VERSION 5.7 ;
BUSBITCHARS "[]" ;
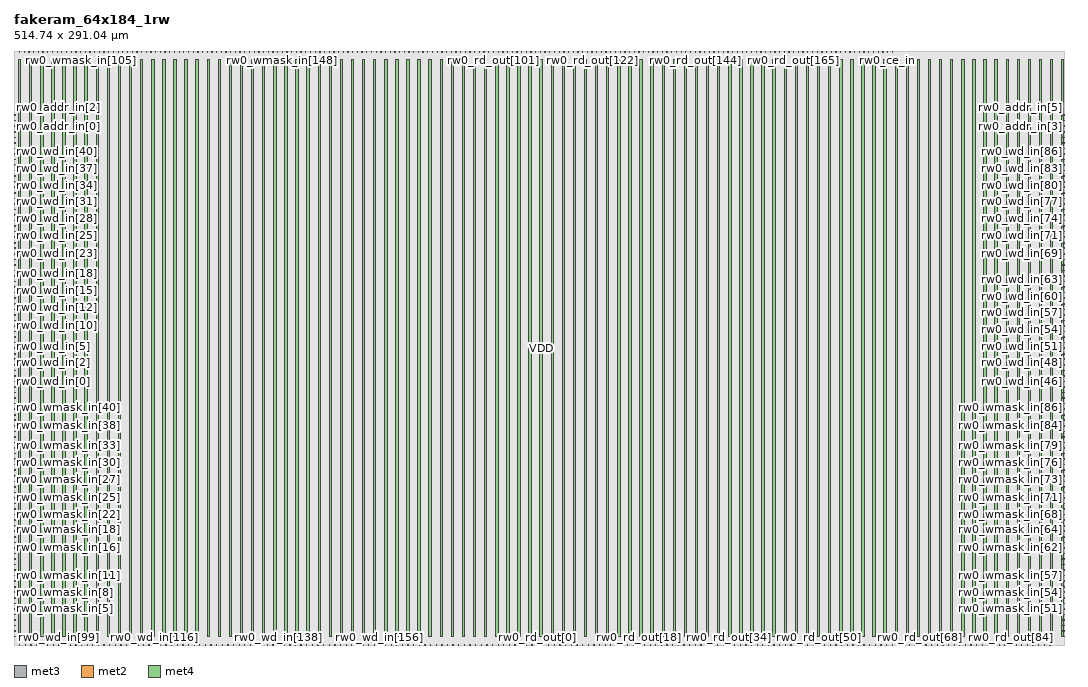
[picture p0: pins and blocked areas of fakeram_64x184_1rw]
MACRO fakeram_64x184_1rw
  FOREIGN fakeram_64x184_1rw 0 0 ;
  SYMMETRY X Y R90 ;
  SIZE 514.740 BY 291.040 ;
  CLASS BLOCK ;
  PIN rw0_wmask_in[0]
    DIRECTION INPUT ;
    USE SIGNAL ;
    SHAPE ABUTMENT ;
    PORT
      LAYER met3 ;
      RECT 0.000 3.930 0.900 4.230 ;
    END
  END rw0_wmask_in[0]
  PIN rw0_wmask_in[1]
    DIRECTION INPUT ;
    USE SIGNAL ;
    SHAPE ABUTMENT ;
    PORT
      LAYER met3 ;
      RECT 0.000 6.650 0.900 6.950 ;
    END
  END rw0_wmask_in[1]
  PIN rw0_wmask_in[2]
    DIRECTION INPUT ;
    USE SIGNAL ;
    SHAPE ABUTMENT ;
    PORT
      LAYER met3 ;
      RECT 0.000 9.370 0.900 9.670 ;
    END
  END rw0_wmask_in[2]
  PIN rw0_wmask_in[3]
    DIRECTION INPUT ;
    USE SIGNAL ;
    SHAPE ABUTMENT ;
    PORT
      LAYER met3 ;
      RECT 0.000 12.090 0.900 12.390 ;
    END
  END rw0_wmask_in[3]
  PIN rw0_wmask_in[4]
    DIRECTION INPUT ;
    USE SIGNAL ;
    SHAPE ABUTMENT ;
    PORT
      LAYER met3 ;
      RECT 0.000 14.810 0.900 15.110 ;
    END
  END rw0_wmask_in[4]
  PIN rw0_wmask_in[5]
    DIRECTION INPUT ;
    USE SIGNAL ;
    SHAPE ABUTMENT ;
    PORT
      LAYER met3 ;
      RECT 0.000 17.530 0.900 17.830 ;
    END
  END rw0_wmask_in[5]
  PIN rw0_wmask_in[6]
    DIRECTION INPUT ;
    USE SIGNAL ;
    SHAPE ABUTMENT ;
    PORT
      LAYER met3 ;
      RECT 0.000 20.250 0.900 20.550 ;
    END
  END rw0_wmask_in[6]
  PIN rw0_wmask_in[7]
    DIRECTION INPUT ;
    USE SIGNAL ;
    SHAPE ABUTMENT ;
    PORT
      LAYER met3 ;
      RECT 0.000 22.970 0.900 23.270 ;
    END
  END rw0_wmask_in[7]
  PIN rw0_wmask_in[8]
    DIRECTION INPUT ;
    USE SIGNAL ;
    SHAPE ABUTMENT ;
    PORT
      LAYER met3 ;
      RECT 0.000 25.690 0.900 25.990 ;
    END
  END rw0_wmask_in[8]
  PIN rw0_wmask_in[9]
    DIRECTION INPUT ;
    USE SIGNAL ;
    SHAPE ABUTMENT ;
    PORT
      LAYER met3 ;
      RECT 0.000 28.410 0.900 28.710 ;
    END
  END rw0_wmask_in[9]
  PIN rw0_wmask_in[10]
    DIRECTION INPUT ;
    USE SIGNAL ;
    SHAPE ABUTMENT ;
    PORT
      LAYER met3 ;
      RECT 0.000 31.130 0.900 31.430 ;
    END
  END rw0_wmask_in[10]
  PIN rw0_wmask_in[11]
    DIRECTION INPUT ;
    USE SIGNAL ;
    SHAPE ABUTMENT ;
    PORT
      LAYER met3 ;
      RECT 0.000 33.850 0.900 34.150 ;
    END
  END rw0_wmask_in[11]
  PIN rw0_wmask_in[12]
    DIRECTION INPUT ;
    USE SIGNAL ;
    SHAPE ABUTMENT ;
    PORT
      LAYER met3 ;
      RECT 0.000 36.570 0.900 36.870 ;
    END
  END rw0_wmask_in[12]
  PIN rw0_wmask_in[13]
    DIRECTION INPUT ;
    USE SIGNAL ;
    SHAPE ABUTMENT ;
    PORT
      LAYER met3 ;
      RECT 0.000 39.290 0.900 39.590 ;
    END
  END rw0_wmask_in[13]
  PIN rw0_wmask_in[14]
    DIRECTION INPUT ;
    USE SIGNAL ;
    SHAPE ABUTMENT ;
    PORT
      LAYER met3 ;
      RECT 0.000 42.010 0.900 42.310 ;
    END
  END rw0_wmask_in[14]
  PIN rw0_wmask_in[15]
    DIRECTION INPUT ;
    USE SIGNAL ;
    SHAPE ABUTMENT ;
    PORT
      LAYER met3 ;
      RECT 0.000 44.730 0.900 45.030 ;
    END
  END rw0_wmask_in[15]
  PIN rw0_wmask_in[16]
    DIRECTION INPUT ;
    USE SIGNAL ;
    SHAPE ABUTMENT ;
    PORT
      LAYER met3 ;
      RECT 0.000 47.450 0.900 47.750 ;
    END
  END rw0_wmask_in[16]
  PIN rw0_wmask_in[17]
    DIRECTION INPUT ;
    USE SIGNAL ;
    SHAPE ABUTMENT ;
    PORT
      LAYER met3 ;
      RECT 0.000 50.170 0.900 50.470 ;
    END
  END rw0_wmask_in[17]
  PIN rw0_wmask_in[18]
    DIRECTION INPUT ;
    USE SIGNAL ;
    SHAPE ABUTMENT ;
    PORT
      LAYER met3 ;
      RECT 0.000 52.890 0.900 53.190 ;
    END
  END rw0_wmask_in[18]
  PIN rw0_wmask_in[19]
    DIRECTION INPUT ;
    USE SIGNAL ;
    SHAPE ABUTMENT ;
    PORT
      LAYER met3 ;
      RECT 0.000 55.610 0.900 55.910 ;
    END
  END rw0_wmask_in[19]
  PIN rw0_wmask_in[20]
    DIRECTION INPUT ;
    USE SIGNAL ;
    SHAPE ABUTMENT ;
    PORT
      LAYER met3 ;
      RECT 0.000 58.330 0.900 58.630 ;
    END
  END rw0_wmask_in[20]
  PIN rw0_wmask_in[21]
    DIRECTION INPUT ;
    USE SIGNAL ;
    SHAPE ABUTMENT ;
    PORT
      LAYER met3 ;
      RECT 0.000 61.050 0.900 61.350 ;
    END
  END rw0_wmask_in[21]
  PIN rw0_wmask_in[22]
    DIRECTION INPUT ;
    USE SIGNAL ;
    SHAPE ABUTMENT ;
    PORT
      LAYER met3 ;
      RECT 0.000 63.770 0.900 64.070 ;
    END
  END rw0_wmask_in[22]
  PIN rw0_wmask_in[23]
    DIRECTION INPUT ;
    USE SIGNAL ;
    SHAPE ABUTMENT ;
    PORT
      LAYER met3 ;
      RECT 0.000 66.490 0.900 66.790 ;
    END
  END rw0_wmask_in[23]
  PIN rw0_wmask_in[24]
    DIRECTION INPUT ;
    USE SIGNAL ;
    SHAPE ABUTMENT ;
    PORT
      LAYER met3 ;
      RECT 0.000 69.210 0.900 69.510 ;
    END
  END rw0_wmask_in[24]
  PIN rw0_wmask_in[25]
    DIRECTION INPUT ;
    USE SIGNAL ;
    SHAPE ABUTMENT ;
    PORT
      LAYER met3 ;
      RECT 0.000 71.930 0.900 72.230 ;
    END
  END rw0_wmask_in[25]
  PIN rw0_wmask_in[26]
    DIRECTION INPUT ;
    USE SIGNAL ;
    SHAPE ABUTMENT ;
    PORT
      LAYER met3 ;
      RECT 0.000 74.650 0.900 74.950 ;
    END
  END rw0_wmask_in[26]
  PIN rw0_wmask_in[27]
    DIRECTION INPUT ;
    USE SIGNAL ;
    SHAPE ABUTMENT ;
    PORT
      LAYER met3 ;
      RECT 0.000 77.370 0.900 77.670 ;
    END
  END rw0_wmask_in[27]
  PIN rw0_wmask_in[28]
    DIRECTION INPUT ;
    USE SIGNAL ;
    SHAPE ABUTMENT ;
    PORT
      LAYER met3 ;
      RECT 0.000 80.090 0.900 80.390 ;
    END
  END rw0_wmask_in[28]
  PIN rw0_wmask_in[29]
    DIRECTION INPUT ;
    USE SIGNAL ;
    SHAPE ABUTMENT ;
    PORT
      LAYER met3 ;
      RECT 0.000 82.810 0.900 83.110 ;
    END
  END rw0_wmask_in[29]
  PIN rw0_wmask_in[30]
    DIRECTION INPUT ;
    USE SIGNAL ;
    SHAPE ABUTMENT ;
    PORT
      LAYER met3 ;
      RECT 0.000 85.530 0.900 85.830 ;
    END
  END rw0_wmask_in[30]
  PIN rw0_wmask_in[31]
    DIRECTION INPUT ;
    USE SIGNAL ;
    SHAPE ABUTMENT ;
    PORT
      LAYER met3 ;
      RECT 0.000 88.250 0.900 88.550 ;
    END
  END rw0_wmask_in[31]
  PIN rw0_wmask_in[32]
    DIRECTION INPUT ;
    USE SIGNAL ;
    SHAPE ABUTMENT ;
    PORT
      LAYER met3 ;
      RECT 0.000 90.970 0.900 91.270 ;
    END
  END rw0_wmask_in[32]
  PIN rw0_wmask_in[33]
    DIRECTION INPUT ;
    USE SIGNAL ;
    SHAPE ABUTMENT ;
    PORT
      LAYER met3 ;
      RECT 0.000 93.690 0.900 93.990 ;
    END
  END rw0_wmask_in[33]
  PIN rw0_wmask_in[34]
    DIRECTION INPUT ;
    USE SIGNAL ;
    SHAPE ABUTMENT ;
    PORT
      LAYER met3 ;
      RECT 0.000 96.410 0.900 96.710 ;
    END
  END rw0_wmask_in[34]
  PIN rw0_wmask_in[35]
    DIRECTION INPUT ;
    USE SIGNAL ;
    SHAPE ABUTMENT ;
    PORT
      LAYER met3 ;
      RECT 0.000 99.130 0.900 99.430 ;
    END
  END rw0_wmask_in[35]
  PIN rw0_wmask_in[36]
    DIRECTION INPUT ;
    USE SIGNAL ;
    SHAPE ABUTMENT ;
    PORT
      LAYER met3 ;
      RECT 0.000 101.850 0.900 102.150 ;
    END
  END rw0_wmask_in[36]
  PIN rw0_wmask_in[37]
    DIRECTION INPUT ;
    USE SIGNAL ;
    SHAPE ABUTMENT ;
    PORT
      LAYER met3 ;
      RECT 0.000 104.570 0.900 104.870 ;
    END
  END rw0_wmask_in[37]
  PIN rw0_wmask_in[38]
    DIRECTION INPUT ;
    USE SIGNAL ;
    SHAPE ABUTMENT ;
    PORT
      LAYER met3 ;
      RECT 0.000 107.290 0.900 107.590 ;
    END
  END rw0_wmask_in[38]
  PIN rw0_wmask_in[39]
    DIRECTION INPUT ;
    USE SIGNAL ;
    SHAPE ABUTMENT ;
    PORT
      LAYER met3 ;
      RECT 0.000 110.010 0.900 110.310 ;
    END
  END rw0_wmask_in[39]
  PIN rw0_wmask_in[40]
    DIRECTION INPUT ;
    USE SIGNAL ;
    SHAPE ABUTMENT ;
    PORT
      LAYER met3 ;
      RECT 0.000 112.730 0.900 113.030 ;
    END
  END rw0_wmask_in[40]
  PIN rw0_wmask_in[41]
    DIRECTION INPUT ;
    USE SIGNAL ;
    SHAPE ABUTMENT ;
    PORT
      LAYER met3 ;
      RECT 0.000 115.450 0.900 115.750 ;
    END
  END rw0_wmask_in[41]
  PIN rw0_wmask_in[42]
    DIRECTION INPUT ;
    USE SIGNAL ;
    SHAPE ABUTMENT ;
    PORT
      LAYER met3 ;
      RECT 0.000 118.170 0.900 118.470 ;
    END
  END rw0_wmask_in[42]
  PIN rw0_wmask_in[43]
    DIRECTION INPUT ;
    USE SIGNAL ;
    SHAPE ABUTMENT ;
    PORT
      LAYER met3 ;
      RECT 0.000 120.890 0.900 121.190 ;
    END
  END rw0_wmask_in[43]
  PIN rw0_wmask_in[44]
    DIRECTION INPUT ;
    USE SIGNAL ;
    SHAPE ABUTMENT ;
    PORT
      LAYER met3 ;
      RECT 0.000 123.610 0.900 123.910 ;
    END
  END rw0_wmask_in[44]
  PIN rw0_wmask_in[45]
    DIRECTION INPUT ;
    USE SIGNAL ;
    SHAPE ABUTMENT ;
    PORT
      LAYER met3 ;
      RECT 0.000 126.330 0.900 126.630 ;
    END
  END rw0_wmask_in[45]
  PIN rw0_wmask_in[46]
    DIRECTION INPUT ;
    USE SIGNAL ;
    SHAPE ABUTMENT ;
    PORT
      LAYER met3 ;
      RECT 513.840 3.930 514.740 4.230 ;
    END
  END rw0_wmask_in[46]
  PIN rw0_wmask_in[47]
    DIRECTION INPUT ;
    USE SIGNAL ;
    SHAPE ABUTMENT ;
    PORT
      LAYER met3 ;
      RECT 513.840 6.650 514.740 6.950 ;
    END
  END rw0_wmask_in[47]
  PIN rw0_wmask_in[48]
    DIRECTION INPUT ;
    USE SIGNAL ;
    SHAPE ABUTMENT ;
    PORT
      LAYER met3 ;
      RECT 513.840 9.370 514.740 9.670 ;
    END
  END rw0_wmask_in[48]
  PIN rw0_wmask_in[49]
    DIRECTION INPUT ;
    USE SIGNAL ;
    SHAPE ABUTMENT ;
    PORT
      LAYER met3 ;
      RECT 513.840 12.090 514.740 12.390 ;
    END
  END rw0_wmask_in[49]
  PIN rw0_wmask_in[50]
    DIRECTION INPUT ;
    USE SIGNAL ;
    SHAPE ABUTMENT ;
    PORT
      LAYER met3 ;
      RECT 513.840 14.810 514.740 15.110 ;
    END
  END rw0_wmask_in[50]
  PIN rw0_wmask_in[51]
    DIRECTION INPUT ;
    USE SIGNAL ;
    SHAPE ABUTMENT ;
    PORT
      LAYER met3 ;
      RECT 513.840 17.530 514.740 17.830 ;
    END
  END rw0_wmask_in[51]
  PIN rw0_wmask_in[52]
    DIRECTION INPUT ;
    USE SIGNAL ;
    SHAPE ABUTMENT ;
    PORT
      LAYER met3 ;
      RECT 513.840 20.250 514.740 20.550 ;
    END
  END rw0_wmask_in[52]
  PIN rw0_wmask_in[53]
    DIRECTION INPUT ;
    USE SIGNAL ;
    SHAPE ABUTMENT ;
    PORT
      LAYER met3 ;
      RECT 513.840 22.970 514.740 23.270 ;
    END
  END rw0_wmask_in[53]
  PIN rw0_wmask_in[54]
    DIRECTION INPUT ;
    USE SIGNAL ;
    SHAPE ABUTMENT ;
    PORT
      LAYER met3 ;
      RECT 513.840 25.690 514.740 25.990 ;
    END
  END rw0_wmask_in[54]
  PIN rw0_wmask_in[55]
    DIRECTION INPUT ;
    USE SIGNAL ;
    SHAPE ABUTMENT ;
    PORT
      LAYER met3 ;
      RECT 513.840 28.410 514.740 28.710 ;
    END
  END rw0_wmask_in[55]
  PIN rw0_wmask_in[56]
    DIRECTION INPUT ;
    USE SIGNAL ;
    SHAPE ABUTMENT ;
    PORT
      LAYER met3 ;
      RECT 513.840 31.130 514.740 31.430 ;
    END
  END rw0_wmask_in[56]
  PIN rw0_wmask_in[57]
    DIRECTION INPUT ;
    USE SIGNAL ;
    SHAPE ABUTMENT ;
    PORT
      LAYER met3 ;
      RECT 513.840 33.850 514.740 34.150 ;
    END
  END rw0_wmask_in[57]
  PIN rw0_wmask_in[58]
    DIRECTION INPUT ;
    USE SIGNAL ;
    SHAPE ABUTMENT ;
    PORT
      LAYER met3 ;
      RECT 513.840 36.570 514.740 36.870 ;
    END
  END rw0_wmask_in[58]
  PIN rw0_wmask_in[59]
    DIRECTION INPUT ;
    USE SIGNAL ;
    SHAPE ABUTMENT ;
    PORT
      LAYER met3 ;
      RECT 513.840 39.290 514.740 39.590 ;
    END
  END rw0_wmask_in[59]
  PIN rw0_wmask_in[60]
    DIRECTION INPUT ;
    USE SIGNAL ;
    SHAPE ABUTMENT ;
    PORT
      LAYER met3 ;
      RECT 513.840 42.010 514.740 42.310 ;
    END
  END rw0_wmask_in[60]
  PIN rw0_wmask_in[61]
    DIRECTION INPUT ;
    USE SIGNAL ;
    SHAPE ABUTMENT ;
    PORT
      LAYER met3 ;
      RECT 513.840 44.730 514.740 45.030 ;
    END
  END rw0_wmask_in[61]
  PIN rw0_wmask_in[62]
    DIRECTION INPUT ;
    USE SIGNAL ;
    SHAPE ABUTMENT ;
    PORT
      LAYER met3 ;
      RECT 513.840 47.450 514.740 47.750 ;
    END
  END rw0_wmask_in[62]
  PIN rw0_wmask_in[63]
    DIRECTION INPUT ;
    USE SIGNAL ;
    SHAPE ABUTMENT ;
    PORT
      LAYER met3 ;
      RECT 513.840 50.170 514.740 50.470 ;
    END
  END rw0_wmask_in[63]
  PIN rw0_wmask_in[64]
    DIRECTION INPUT ;
    USE SIGNAL ;
    SHAPE ABUTMENT ;
    PORT
      LAYER met3 ;
      RECT 513.840 52.890 514.740 53.190 ;
    END
  END rw0_wmask_in[64]
  PIN rw0_wmask_in[65]
    DIRECTION INPUT ;
    USE SIGNAL ;
    SHAPE ABUTMENT ;
    PORT
      LAYER met3 ;
      RECT 513.840 55.610 514.740 55.910 ;
    END
  END rw0_wmask_in[65]
  PIN rw0_wmask_in[66]
    DIRECTION INPUT ;
    USE SIGNAL ;
    SHAPE ABUTMENT ;
    PORT
      LAYER met3 ;
      RECT 513.840 58.330 514.740 58.630 ;
    END
  END rw0_wmask_in[66]
  PIN rw0_wmask_in[67]
    DIRECTION INPUT ;
    USE SIGNAL ;
    SHAPE ABUTMENT ;
    PORT
      LAYER met3 ;
      RECT 513.840 61.050 514.740 61.350 ;
    END
  END rw0_wmask_in[67]
  PIN rw0_wmask_in[68]
    DIRECTION INPUT ;
    USE SIGNAL ;
    SHAPE ABUTMENT ;
    PORT
      LAYER met3 ;
      RECT 513.840 63.770 514.740 64.070 ;
    END
  END rw0_wmask_in[68]
  PIN rw0_wmask_in[69]
    DIRECTION INPUT ;
    USE SIGNAL ;
    SHAPE ABUTMENT ;
    PORT
      LAYER met3 ;
      RECT 513.840 66.490 514.740 66.790 ;
    END
  END rw0_wmask_in[69]
  PIN rw0_wmask_in[70]
    DIRECTION INPUT ;
    USE SIGNAL ;
    SHAPE ABUTMENT ;
    PORT
      LAYER met3 ;
      RECT 513.840 69.210 514.740 69.510 ;
    END
  END rw0_wmask_in[70]
  PIN rw0_wmask_in[71]
    DIRECTION INPUT ;
    USE SIGNAL ;
    SHAPE ABUTMENT ;
    PORT
      LAYER met3 ;
      RECT 513.840 71.930 514.740 72.230 ;
    END
  END rw0_wmask_in[71]
  PIN rw0_wmask_in[72]
    DIRECTION INPUT ;
    USE SIGNAL ;
    SHAPE ABUTMENT ;
    PORT
      LAYER met3 ;
      RECT 513.840 74.650 514.740 74.950 ;
    END
  END rw0_wmask_in[72]
  PIN rw0_wmask_in[73]
    DIRECTION INPUT ;
    USE SIGNAL ;
    SHAPE ABUTMENT ;
    PORT
      LAYER met3 ;
      RECT 513.840 77.370 514.740 77.670 ;
    END
  END rw0_wmask_in[73]
  PIN rw0_wmask_in[74]
    DIRECTION INPUT ;
    USE SIGNAL ;
    SHAPE ABUTMENT ;
    PORT
      LAYER met3 ;
      RECT 513.840 80.090 514.740 80.390 ;
    END
  END rw0_wmask_in[74]
  PIN rw0_wmask_in[75]
    DIRECTION INPUT ;
    USE SIGNAL ;
    SHAPE ABUTMENT ;
    PORT
      LAYER met3 ;
      RECT 513.840 82.810 514.740 83.110 ;
    END
  END rw0_wmask_in[75]
  PIN rw0_wmask_in[76]
    DIRECTION INPUT ;
    USE SIGNAL ;
    SHAPE ABUTMENT ;
    PORT
      LAYER met3 ;
      RECT 513.840 85.530 514.740 85.830 ;
    END
  END rw0_wmask_in[76]
  PIN rw0_wmask_in[77]
    DIRECTION INPUT ;
    USE SIGNAL ;
    SHAPE ABUTMENT ;
    PORT
      LAYER met3 ;
      RECT 513.840 88.250 514.740 88.550 ;
    END
  END rw0_wmask_in[77]
  PIN rw0_wmask_in[78]
    DIRECTION INPUT ;
    USE SIGNAL ;
    SHAPE ABUTMENT ;
    PORT
      LAYER met3 ;
      RECT 513.840 90.970 514.740 91.270 ;
    END
  END rw0_wmask_in[78]
  PIN rw0_wmask_in[79]
    DIRECTION INPUT ;
    USE SIGNAL ;
    SHAPE ABUTMENT ;
    PORT
      LAYER met3 ;
      RECT 513.840 93.690 514.740 93.990 ;
    END
  END rw0_wmask_in[79]
  PIN rw0_wmask_in[80]
    DIRECTION INPUT ;
    USE SIGNAL ;
    SHAPE ABUTMENT ;
    PORT
      LAYER met3 ;
      RECT 513.840 96.410 514.740 96.710 ;
    END
  END rw0_wmask_in[80]
  PIN rw0_wmask_in[81]
    DIRECTION INPUT ;
    USE SIGNAL ;
    SHAPE ABUTMENT ;
    PORT
      LAYER met3 ;
      RECT 513.840 99.130 514.740 99.430 ;
    END
  END rw0_wmask_in[81]
  PIN rw0_wmask_in[82]
    DIRECTION INPUT ;
    USE SIGNAL ;
    SHAPE ABUTMENT ;
    PORT
      LAYER met3 ;
      RECT 513.840 101.850 514.740 102.150 ;
    END
  END rw0_wmask_in[82]
  PIN rw0_wmask_in[83]
    DIRECTION INPUT ;
    USE SIGNAL ;
    SHAPE ABUTMENT ;
    PORT
      LAYER met3 ;
      RECT 513.840 104.570 514.740 104.870 ;
    END
  END rw0_wmask_in[83]
  PIN rw0_wmask_in[84]
    DIRECTION INPUT ;
    USE SIGNAL ;
    SHAPE ABUTMENT ;
    PORT
      LAYER met3 ;
      RECT 513.840 107.290 514.740 107.590 ;
    END
  END rw0_wmask_in[84]
  PIN rw0_wmask_in[85]
    DIRECTION INPUT ;
    USE SIGNAL ;
    SHAPE ABUTMENT ;
    PORT
      LAYER met3 ;
      RECT 513.840 110.010 514.740 110.310 ;
    END
  END rw0_wmask_in[85]
  PIN rw0_wmask_in[86]
    DIRECTION INPUT ;
    USE SIGNAL ;
    SHAPE ABUTMENT ;
    PORT
      LAYER met3 ;
      RECT 513.840 112.730 514.740 113.030 ;
    END
  END rw0_wmask_in[86]
  PIN rw0_wmask_in[87]
    DIRECTION INPUT ;
    USE SIGNAL ;
    SHAPE ABUTMENT ;
    PORT
      LAYER met3 ;
      RECT 513.840 115.450 514.740 115.750 ;
    END
  END rw0_wmask_in[87]
  PIN rw0_wmask_in[88]
    DIRECTION INPUT ;
    USE SIGNAL ;
    SHAPE ABUTMENT ;
    PORT
      LAYER met3 ;
      RECT 513.840 118.170 514.740 118.470 ;
    END
  END rw0_wmask_in[88]
  PIN rw0_wmask_in[89]
    DIRECTION INPUT ;
    USE SIGNAL ;
    SHAPE ABUTMENT ;
    PORT
      LAYER met3 ;
      RECT 513.840 120.890 514.740 121.190 ;
    END
  END rw0_wmask_in[89]
  PIN rw0_wmask_in[90]
    DIRECTION INPUT ;
    USE SIGNAL ;
    SHAPE ABUTMENT ;
    PORT
      LAYER met3 ;
      RECT 513.840 123.610 514.740 123.910 ;
    END
  END rw0_wmask_in[90]
  PIN rw0_wmask_in[91]
    DIRECTION INPUT ;
    USE SIGNAL ;
    SHAPE ABUTMENT ;
    PORT
      LAYER met3 ;
      RECT 513.840 126.330 514.740 126.630 ;
    END
  END rw0_wmask_in[91]
  PIN rw0_wmask_in[92]
    DIRECTION INPUT ;
    USE SIGNAL ;
    SHAPE ABUTMENT ;
    PORT
      LAYER met2 ;
      RECT 2.690 290.620 2.830 291.040 ;
    END
  END rw0_wmask_in[92]
  PIN rw0_wmask_in[93]
    DIRECTION INPUT ;
    USE SIGNAL ;
    SHAPE ABUTMENT ;
    PORT
      LAYER met2 ;
      RECT 4.990 290.620 5.130 291.040 ;
    END
  END rw0_wmask_in[93]
  PIN rw0_wmask_in[94]
    DIRECTION INPUT ;
    USE SIGNAL ;
    SHAPE ABUTMENT ;
    PORT
      LAYER met2 ;
      RECT 7.290 290.620 7.430 291.040 ;
    END
  END rw0_wmask_in[94]
  PIN rw0_wmask_in[95]
    DIRECTION INPUT ;
    USE SIGNAL ;
    SHAPE ABUTMENT ;
    PORT
      LAYER met2 ;
      RECT 9.590 290.620 9.730 291.040 ;
    END
  END rw0_wmask_in[95]
  PIN rw0_wmask_in[96]
    DIRECTION INPUT ;
    USE SIGNAL ;
    SHAPE ABUTMENT ;
    PORT
      LAYER met2 ;
      RECT 11.890 290.620 12.030 291.040 ;
    END
  END rw0_wmask_in[96]
  PIN rw0_wmask_in[97]
    DIRECTION INPUT ;
    USE SIGNAL ;
    SHAPE ABUTMENT ;
    PORT
      LAYER met2 ;
      RECT 14.190 290.620 14.330 291.040 ;
    END
  END rw0_wmask_in[97]
  PIN rw0_wmask_in[98]
    DIRECTION INPUT ;
    USE SIGNAL ;
    SHAPE ABUTMENT ;
    PORT
      LAYER met2 ;
      RECT 16.490 290.620 16.630 291.040 ;
    END
  END rw0_wmask_in[98]
  PIN rw0_wmask_in[99]
    DIRECTION INPUT ;
    USE SIGNAL ;
    SHAPE ABUTMENT ;
    PORT
      LAYER met2 ;
      RECT 18.790 290.620 18.930 291.040 ;
    END
  END rw0_wmask_in[99]
  PIN rw0_wmask_in[100]
    DIRECTION INPUT ;
    USE SIGNAL ;
    SHAPE ABUTMENT ;
    PORT
      LAYER met2 ;
      RECT 21.090 290.620 21.230 291.040 ;
    END
  END rw0_wmask_in[100]
  PIN rw0_wmask_in[101]
    DIRECTION INPUT ;
    USE SIGNAL ;
    SHAPE ABUTMENT ;
    PORT
      LAYER met2 ;
      RECT 23.390 290.620 23.530 291.040 ;
    END
  END rw0_wmask_in[101]
  PIN rw0_wmask_in[102]
    DIRECTION INPUT ;
    USE SIGNAL ;
    SHAPE ABUTMENT ;
    PORT
      LAYER met2 ;
      RECT 25.690 290.620 25.830 291.040 ;
    END
  END rw0_wmask_in[102]
  PIN rw0_wmask_in[103]
    DIRECTION INPUT ;
    USE SIGNAL ;
    SHAPE ABUTMENT ;
    PORT
      LAYER met2 ;
      RECT 27.990 290.620 28.130 291.040 ;
    END
  END rw0_wmask_in[103]
  PIN rw0_wmask_in[104]
    DIRECTION INPUT ;
    USE SIGNAL ;
    SHAPE ABUTMENT ;
    PORT
      LAYER met2 ;
      RECT 30.290 290.620 30.430 291.040 ;
    END
  END rw0_wmask_in[104]
  PIN rw0_wmask_in[105]
    DIRECTION INPUT ;
    USE SIGNAL ;
    SHAPE ABUTMENT ;
    PORT
      LAYER met2 ;
      RECT 32.590 290.620 32.730 291.040 ;
    END
  END rw0_wmask_in[105]
  PIN rw0_wmask_in[106]
    DIRECTION INPUT ;
    USE SIGNAL ;
    SHAPE ABUTMENT ;
    PORT
      LAYER met2 ;
      RECT 34.890 290.620 35.030 291.040 ;
    END
  END rw0_wmask_in[106]
  PIN rw0_wmask_in[107]
    DIRECTION INPUT ;
    USE SIGNAL ;
    SHAPE ABUTMENT ;
    PORT
      LAYER met2 ;
      RECT 37.190 290.620 37.330 291.040 ;
    END
  END rw0_wmask_in[107]
  PIN rw0_wmask_in[108]
    DIRECTION INPUT ;
    USE SIGNAL ;
    SHAPE ABUTMENT ;
    PORT
      LAYER met2 ;
      RECT 39.490 290.620 39.630 291.040 ;
    END
  END rw0_wmask_in[108]
  PIN rw0_wmask_in[109]
    DIRECTION INPUT ;
    USE SIGNAL ;
    SHAPE ABUTMENT ;
    PORT
      LAYER met2 ;
      RECT 41.790 290.620 41.930 291.040 ;
    END
  END rw0_wmask_in[109]
  PIN rw0_wmask_in[110]
    DIRECTION INPUT ;
    USE SIGNAL ;
    SHAPE ABUTMENT ;
    PORT
      LAYER met2 ;
      RECT 44.090 290.620 44.230 291.040 ;
    END
  END rw0_wmask_in[110]
  PIN rw0_wmask_in[111]
    DIRECTION INPUT ;
    USE SIGNAL ;
    SHAPE ABUTMENT ;
    PORT
      LAYER met2 ;
      RECT 46.390 290.620 46.530 291.040 ;
    END
  END rw0_wmask_in[111]
  PIN rw0_wmask_in[112]
    DIRECTION INPUT ;
    USE SIGNAL ;
    SHAPE ABUTMENT ;
    PORT
      LAYER met2 ;
      RECT 48.690 290.620 48.830 291.040 ;
    END
  END rw0_wmask_in[112]
  PIN rw0_wmask_in[113]
    DIRECTION INPUT ;
    USE SIGNAL ;
    SHAPE ABUTMENT ;
    PORT
      LAYER met2 ;
      RECT 50.990 290.620 51.130 291.040 ;
    END
  END rw0_wmask_in[113]
  PIN rw0_wmask_in[114]
    DIRECTION INPUT ;
    USE SIGNAL ;
    SHAPE ABUTMENT ;
    PORT
      LAYER met2 ;
      RECT 53.290 290.620 53.430 291.040 ;
    END
  END rw0_wmask_in[114]
  PIN rw0_wmask_in[115]
    DIRECTION INPUT ;
    USE SIGNAL ;
    SHAPE ABUTMENT ;
    PORT
      LAYER met2 ;
      RECT 55.590 290.620 55.730 291.040 ;
    END
  END rw0_wmask_in[115]
  PIN rw0_wmask_in[116]
    DIRECTION INPUT ;
    USE SIGNAL ;
    SHAPE ABUTMENT ;
    PORT
      LAYER met2 ;
      RECT 57.890 290.620 58.030 291.040 ;
    END
  END rw0_wmask_in[116]
  PIN rw0_wmask_in[117]
    DIRECTION INPUT ;
    USE SIGNAL ;
    SHAPE ABUTMENT ;
    PORT
      LAYER met2 ;
      RECT 60.190 290.620 60.330 291.040 ;
    END
  END rw0_wmask_in[117]
  PIN rw0_wmask_in[118]
    DIRECTION INPUT ;
    USE SIGNAL ;
    SHAPE ABUTMENT ;
    PORT
      LAYER met2 ;
      RECT 62.490 290.620 62.630 291.040 ;
    END
  END rw0_wmask_in[118]
  PIN rw0_wmask_in[119]
    DIRECTION INPUT ;
    USE SIGNAL ;
    SHAPE ABUTMENT ;
    PORT
      LAYER met2 ;
      RECT 64.790 290.620 64.930 291.040 ;
    END
  END rw0_wmask_in[119]
  PIN rw0_wmask_in[120]
    DIRECTION INPUT ;
    USE SIGNAL ;
    SHAPE ABUTMENT ;
    PORT
      LAYER met2 ;
      RECT 67.090 290.620 67.230 291.040 ;
    END
  END rw0_wmask_in[120]
  PIN rw0_wmask_in[121]
    DIRECTION INPUT ;
    USE SIGNAL ;
    SHAPE ABUTMENT ;
    PORT
      LAYER met2 ;
      RECT 69.390 290.620 69.530 291.040 ;
    END
  END rw0_wmask_in[121]
  PIN rw0_wmask_in[122]
    DIRECTION INPUT ;
    USE SIGNAL ;
    SHAPE ABUTMENT ;
    PORT
      LAYER met2 ;
      RECT 71.690 290.620 71.830 291.040 ;
    END
  END rw0_wmask_in[122]
  PIN rw0_wmask_in[123]
    DIRECTION INPUT ;
    USE SIGNAL ;
    SHAPE ABUTMENT ;
    PORT
      LAYER met2 ;
      RECT 73.990 290.620 74.130 291.040 ;
    END
  END rw0_wmask_in[123]
  PIN rw0_wmask_in[124]
    DIRECTION INPUT ;
    USE SIGNAL ;
    SHAPE ABUTMENT ;
    PORT
      LAYER met2 ;
      RECT 76.290 290.620 76.430 291.040 ;
    END
  END rw0_wmask_in[124]
  PIN rw0_wmask_in[125]
    DIRECTION INPUT ;
    USE SIGNAL ;
    SHAPE ABUTMENT ;
    PORT
      LAYER met2 ;
      RECT 78.590 290.620 78.730 291.040 ;
    END
  END rw0_wmask_in[125]
  PIN rw0_wmask_in[126]
    DIRECTION INPUT ;
    USE SIGNAL ;
    SHAPE ABUTMENT ;
    PORT
      LAYER met2 ;
      RECT 80.890 290.620 81.030 291.040 ;
    END
  END rw0_wmask_in[126]
  PIN rw0_wmask_in[127]
    DIRECTION INPUT ;
    USE SIGNAL ;
    SHAPE ABUTMENT ;
    PORT
      LAYER met2 ;
      RECT 83.190 290.620 83.330 291.040 ;
    END
  END rw0_wmask_in[127]
  PIN rw0_wmask_in[128]
    DIRECTION INPUT ;
    USE SIGNAL ;
    SHAPE ABUTMENT ;
    PORT
      LAYER met2 ;
      RECT 85.490 290.620 85.630 291.040 ;
    END
  END rw0_wmask_in[128]
  PIN rw0_wmask_in[129]
    DIRECTION INPUT ;
    USE SIGNAL ;
    SHAPE ABUTMENT ;
    PORT
      LAYER met2 ;
      RECT 87.790 290.620 87.930 291.040 ;
    END
  END rw0_wmask_in[129]
  PIN rw0_wmask_in[130]
    DIRECTION INPUT ;
    USE SIGNAL ;
    SHAPE ABUTMENT ;
    PORT
      LAYER met2 ;
      RECT 90.090 290.620 90.230 291.040 ;
    END
  END rw0_wmask_in[130]
  PIN rw0_wmask_in[131]
    DIRECTION INPUT ;
    USE SIGNAL ;
    SHAPE ABUTMENT ;
    PORT
      LAYER met2 ;
      RECT 92.390 290.620 92.530 291.040 ;
    END
  END rw0_wmask_in[131]
  PIN rw0_wmask_in[132]
    DIRECTION INPUT ;
    USE SIGNAL ;
    SHAPE ABUTMENT ;
    PORT
      LAYER met2 ;
      RECT 94.690 290.620 94.830 291.040 ;
    END
  END rw0_wmask_in[132]
  PIN rw0_wmask_in[133]
    DIRECTION INPUT ;
    USE SIGNAL ;
    SHAPE ABUTMENT ;
    PORT
      LAYER met2 ;
      RECT 96.990 290.620 97.130 291.040 ;
    END
  END rw0_wmask_in[133]
  PIN rw0_wmask_in[134]
    DIRECTION INPUT ;
    USE SIGNAL ;
    SHAPE ABUTMENT ;
    PORT
      LAYER met2 ;
      RECT 99.290 290.620 99.430 291.040 ;
    END
  END rw0_wmask_in[134]
  PIN rw0_wmask_in[135]
    DIRECTION INPUT ;
    USE SIGNAL ;
    SHAPE ABUTMENT ;
    PORT
      LAYER met2 ;
      RECT 101.590 290.620 101.730 291.040 ;
    END
  END rw0_wmask_in[135]
  PIN rw0_wmask_in[136]
    DIRECTION INPUT ;
    USE SIGNAL ;
    SHAPE ABUTMENT ;
    PORT
      LAYER met2 ;
      RECT 103.890 290.620 104.030 291.040 ;
    END
  END rw0_wmask_in[136]
  PIN rw0_wmask_in[137]
    DIRECTION INPUT ;
    USE SIGNAL ;
    SHAPE ABUTMENT ;
    PORT
      LAYER met2 ;
      RECT 106.190 290.620 106.330 291.040 ;
    END
  END rw0_wmask_in[137]
  PIN rw0_wmask_in[138]
    DIRECTION INPUT ;
    USE SIGNAL ;
    SHAPE ABUTMENT ;
    PORT
      LAYER met2 ;
      RECT 108.490 290.620 108.630 291.040 ;
    END
  END rw0_wmask_in[138]
  PIN rw0_wmask_in[139]
    DIRECTION INPUT ;
    USE SIGNAL ;
    SHAPE ABUTMENT ;
    PORT
      LAYER met2 ;
      RECT 110.790 290.620 110.930 291.040 ;
    END
  END rw0_wmask_in[139]
  PIN rw0_wmask_in[140]
    DIRECTION INPUT ;
    USE SIGNAL ;
    SHAPE ABUTMENT ;
    PORT
      LAYER met2 ;
      RECT 113.090 290.620 113.230 291.040 ;
    END
  END rw0_wmask_in[140]
  PIN rw0_wmask_in[141]
    DIRECTION INPUT ;
    USE SIGNAL ;
    SHAPE ABUTMENT ;
    PORT
      LAYER met2 ;
      RECT 115.390 290.620 115.530 291.040 ;
    END
  END rw0_wmask_in[141]
  PIN rw0_wmask_in[142]
    DIRECTION INPUT ;
    USE SIGNAL ;
    SHAPE ABUTMENT ;
    PORT
      LAYER met2 ;
      RECT 117.690 290.620 117.830 291.040 ;
    END
  END rw0_wmask_in[142]
  PIN rw0_wmask_in[143]
    DIRECTION INPUT ;
    USE SIGNAL ;
    SHAPE ABUTMENT ;
    PORT
      LAYER met2 ;
      RECT 119.990 290.620 120.130 291.040 ;
    END
  END rw0_wmask_in[143]
  PIN rw0_wmask_in[144]
    DIRECTION INPUT ;
    USE SIGNAL ;
    SHAPE ABUTMENT ;
    PORT
      LAYER met2 ;
      RECT 122.290 290.620 122.430 291.040 ;
    END
  END rw0_wmask_in[144]
  PIN rw0_wmask_in[145]
    DIRECTION INPUT ;
    USE SIGNAL ;
    SHAPE ABUTMENT ;
    PORT
      LAYER met2 ;
      RECT 124.590 290.620 124.730 291.040 ;
    END
  END rw0_wmask_in[145]
  PIN rw0_wmask_in[146]
    DIRECTION INPUT ;
    USE SIGNAL ;
    SHAPE ABUTMENT ;
    PORT
      LAYER met2 ;
      RECT 126.890 290.620 127.030 291.040 ;
    END
  END rw0_wmask_in[146]
  PIN rw0_wmask_in[147]
    DIRECTION INPUT ;
    USE SIGNAL ;
    SHAPE ABUTMENT ;
    PORT
      LAYER met2 ;
      RECT 129.190 290.620 129.330 291.040 ;
    END
  END rw0_wmask_in[147]
  PIN rw0_wmask_in[148]
    DIRECTION INPUT ;
    USE SIGNAL ;
    SHAPE ABUTMENT ;
    PORT
      LAYER met2 ;
      RECT 131.490 290.620 131.630 291.040 ;
    END
  END rw0_wmask_in[148]
  PIN rw0_wmask_in[149]
    DIRECTION INPUT ;
    USE SIGNAL ;
    SHAPE ABUTMENT ;
    PORT
      LAYER met2 ;
      RECT 133.790 290.620 133.930 291.040 ;
    END
  END rw0_wmask_in[149]
  PIN rw0_wmask_in[150]
    DIRECTION INPUT ;
    USE SIGNAL ;
    SHAPE ABUTMENT ;
    PORT
      LAYER met2 ;
      RECT 136.090 290.620 136.230 291.040 ;
    END
  END rw0_wmask_in[150]
  PIN rw0_wmask_in[151]
    DIRECTION INPUT ;
    USE SIGNAL ;
    SHAPE ABUTMENT ;
    PORT
      LAYER met2 ;
      RECT 138.390 290.620 138.530 291.040 ;
    END
  END rw0_wmask_in[151]
  PIN rw0_wmask_in[152]
    DIRECTION INPUT ;
    USE SIGNAL ;
    SHAPE ABUTMENT ;
    PORT
      LAYER met2 ;
      RECT 140.690 290.620 140.830 291.040 ;
    END
  END rw0_wmask_in[152]
  PIN rw0_wmask_in[153]
    DIRECTION INPUT ;
    USE SIGNAL ;
    SHAPE ABUTMENT ;
    PORT
      LAYER met2 ;
      RECT 142.990 290.620 143.130 291.040 ;
    END
  END rw0_wmask_in[153]
  PIN rw0_wmask_in[154]
    DIRECTION INPUT ;
    USE SIGNAL ;
    SHAPE ABUTMENT ;
    PORT
      LAYER met2 ;
      RECT 145.290 290.620 145.430 291.040 ;
    END
  END rw0_wmask_in[154]
  PIN rw0_wmask_in[155]
    DIRECTION INPUT ;
    USE SIGNAL ;
    SHAPE ABUTMENT ;
    PORT
      LAYER met2 ;
      RECT 147.590 290.620 147.730 291.040 ;
    END
  END rw0_wmask_in[155]
  PIN rw0_wmask_in[156]
    DIRECTION INPUT ;
    USE SIGNAL ;
    SHAPE ABUTMENT ;
    PORT
      LAYER met2 ;
      RECT 149.890 290.620 150.030 291.040 ;
    END
  END rw0_wmask_in[156]
  PIN rw0_wmask_in[157]
    DIRECTION INPUT ;
    USE SIGNAL ;
    SHAPE ABUTMENT ;
    PORT
      LAYER met2 ;
      RECT 152.190 290.620 152.330 291.040 ;
    END
  END rw0_wmask_in[157]
  PIN rw0_wmask_in[158]
    DIRECTION INPUT ;
    USE SIGNAL ;
    SHAPE ABUTMENT ;
    PORT
      LAYER met2 ;
      RECT 154.490 290.620 154.630 291.040 ;
    END
  END rw0_wmask_in[158]
  PIN rw0_wmask_in[159]
    DIRECTION INPUT ;
    USE SIGNAL ;
    SHAPE ABUTMENT ;
    PORT
      LAYER met2 ;
      RECT 156.790 290.620 156.930 291.040 ;
    END
  END rw0_wmask_in[159]
  PIN rw0_wmask_in[160]
    DIRECTION INPUT ;
    USE SIGNAL ;
    SHAPE ABUTMENT ;
    PORT
      LAYER met2 ;
      RECT 159.090 290.620 159.230 291.040 ;
    END
  END rw0_wmask_in[160]
  PIN rw0_wmask_in[161]
    DIRECTION INPUT ;
    USE SIGNAL ;
    SHAPE ABUTMENT ;
    PORT
      LAYER met2 ;
      RECT 161.390 290.620 161.530 291.040 ;
    END
  END rw0_wmask_in[161]
  PIN rw0_wmask_in[162]
    DIRECTION INPUT ;
    USE SIGNAL ;
    SHAPE ABUTMENT ;
    PORT
      LAYER met2 ;
      RECT 163.690 290.620 163.830 291.040 ;
    END
  END rw0_wmask_in[162]
  PIN rw0_wmask_in[163]
    DIRECTION INPUT ;
    USE SIGNAL ;
    SHAPE ABUTMENT ;
    PORT
      LAYER met2 ;
      RECT 165.990 290.620 166.130 291.040 ;
    END
  END rw0_wmask_in[163]
  PIN rw0_wmask_in[164]
    DIRECTION INPUT ;
    USE SIGNAL ;
    SHAPE ABUTMENT ;
    PORT
      LAYER met2 ;
      RECT 168.290 290.620 168.430 291.040 ;
    END
  END rw0_wmask_in[164]
  PIN rw0_wmask_in[165]
    DIRECTION INPUT ;
    USE SIGNAL ;
    SHAPE ABUTMENT ;
    PORT
      LAYER met2 ;
      RECT 170.590 290.620 170.730 291.040 ;
    END
  END rw0_wmask_in[165]
  PIN rw0_wmask_in[166]
    DIRECTION INPUT ;
    USE SIGNAL ;
    SHAPE ABUTMENT ;
    PORT
      LAYER met2 ;
      RECT 172.890 290.620 173.030 291.040 ;
    END
  END rw0_wmask_in[166]
  PIN rw0_wmask_in[167]
    DIRECTION INPUT ;
    USE SIGNAL ;
    SHAPE ABUTMENT ;
    PORT
      LAYER met2 ;
      RECT 175.190 290.620 175.330 291.040 ;
    END
  END rw0_wmask_in[167]
  PIN rw0_wmask_in[168]
    DIRECTION INPUT ;
    USE SIGNAL ;
    SHAPE ABUTMENT ;
    PORT
      LAYER met2 ;
      RECT 177.490 290.620 177.630 291.040 ;
    END
  END rw0_wmask_in[168]
  PIN rw0_wmask_in[169]
    DIRECTION INPUT ;
    USE SIGNAL ;
    SHAPE ABUTMENT ;
    PORT
      LAYER met2 ;
      RECT 179.790 290.620 179.930 291.040 ;
    END
  END rw0_wmask_in[169]
  PIN rw0_wmask_in[170]
    DIRECTION INPUT ;
    USE SIGNAL ;
    SHAPE ABUTMENT ;
    PORT
      LAYER met2 ;
      RECT 182.090 290.620 182.230 291.040 ;
    END
  END rw0_wmask_in[170]
  PIN rw0_wmask_in[171]
    DIRECTION INPUT ;
    USE SIGNAL ;
    SHAPE ABUTMENT ;
    PORT
      LAYER met2 ;
      RECT 184.390 290.620 184.530 291.040 ;
    END
  END rw0_wmask_in[171]
  PIN rw0_wmask_in[172]
    DIRECTION INPUT ;
    USE SIGNAL ;
    SHAPE ABUTMENT ;
    PORT
      LAYER met2 ;
      RECT 186.690 290.620 186.830 291.040 ;
    END
  END rw0_wmask_in[172]
  PIN rw0_wmask_in[173]
    DIRECTION INPUT ;
    USE SIGNAL ;
    SHAPE ABUTMENT ;
    PORT
      LAYER met2 ;
      RECT 188.990 290.620 189.130 291.040 ;
    END
  END rw0_wmask_in[173]
  PIN rw0_wmask_in[174]
    DIRECTION INPUT ;
    USE SIGNAL ;
    SHAPE ABUTMENT ;
    PORT
      LAYER met2 ;
      RECT 191.290 290.620 191.430 291.040 ;
    END
  END rw0_wmask_in[174]
  PIN rw0_wmask_in[175]
    DIRECTION INPUT ;
    USE SIGNAL ;
    SHAPE ABUTMENT ;
    PORT
      LAYER met2 ;
      RECT 193.590 290.620 193.730 291.040 ;
    END
  END rw0_wmask_in[175]
  PIN rw0_wmask_in[176]
    DIRECTION INPUT ;
    USE SIGNAL ;
    SHAPE ABUTMENT ;
    PORT
      LAYER met2 ;
      RECT 195.890 290.620 196.030 291.040 ;
    END
  END rw0_wmask_in[176]
  PIN rw0_wmask_in[177]
    DIRECTION INPUT ;
    USE SIGNAL ;
    SHAPE ABUTMENT ;
    PORT
      LAYER met2 ;
      RECT 198.190 290.620 198.330 291.040 ;
    END
  END rw0_wmask_in[177]
  PIN rw0_wmask_in[178]
    DIRECTION INPUT ;
    USE SIGNAL ;
    SHAPE ABUTMENT ;
    PORT
      LAYER met2 ;
      RECT 200.490 290.620 200.630 291.040 ;
    END
  END rw0_wmask_in[178]
  PIN rw0_wmask_in[179]
    DIRECTION INPUT ;
    USE SIGNAL ;
    SHAPE ABUTMENT ;
    PORT
      LAYER met2 ;
      RECT 202.790 290.620 202.930 291.040 ;
    END
  END rw0_wmask_in[179]
  PIN rw0_wmask_in[180]
    DIRECTION INPUT ;
    USE SIGNAL ;
    SHAPE ABUTMENT ;
    PORT
      LAYER met2 ;
      RECT 205.090 290.620 205.230 291.040 ;
    END
  END rw0_wmask_in[180]
  PIN rw0_wmask_in[181]
    DIRECTION INPUT ;
    USE SIGNAL ;
    SHAPE ABUTMENT ;
    PORT
      LAYER met2 ;
      RECT 207.390 290.620 207.530 291.040 ;
    END
  END rw0_wmask_in[181]
  PIN rw0_wmask_in[182]
    DIRECTION INPUT ;
    USE SIGNAL ;
    SHAPE ABUTMENT ;
    PORT
      LAYER met2 ;
      RECT 209.690 290.620 209.830 291.040 ;
    END
  END rw0_wmask_in[182]
  PIN rw0_wmask_in[183]
    DIRECTION INPUT ;
    USE SIGNAL ;
    SHAPE ABUTMENT ;
    PORT
      LAYER met2 ;
      RECT 211.990 290.620 212.130 291.040 ;
    END
  END rw0_wmask_in[183]
  PIN rw0_wd_in[0]
    DIRECTION INPUT ;
    USE SIGNAL ;
    SHAPE ABUTMENT ;
    PORT
      LAYER met3 ;
      RECT 0.000 129.050 0.900 129.350 ;
    END
  END rw0_wd_in[0]
  PIN rw0_wd_in[1]
    DIRECTION INPUT ;
    USE SIGNAL ;
    SHAPE ABUTMENT ;
    PORT
      LAYER met3 ;
      RECT 0.000 131.770 0.900 132.070 ;
    END
  END rw0_wd_in[1]
  PIN rw0_wd_in[2]
    DIRECTION INPUT ;
    USE SIGNAL ;
    SHAPE ABUTMENT ;
    PORT
      LAYER met3 ;
      RECT 0.000 134.490 0.900 134.790 ;
    END
  END rw0_wd_in[2]
  PIN rw0_wd_in[3]
    DIRECTION INPUT ;
    USE SIGNAL ;
    SHAPE ABUTMENT ;
    PORT
      LAYER met3 ;
      RECT 0.000 137.210 0.900 137.510 ;
    END
  END rw0_wd_in[3]
  PIN rw0_wd_in[4]
    DIRECTION INPUT ;
    USE SIGNAL ;
    SHAPE ABUTMENT ;
    PORT
      LAYER met3 ;
      RECT 0.000 139.930 0.900 140.230 ;
    END
  END rw0_wd_in[4]
  PIN rw0_wd_in[5]
    DIRECTION INPUT ;
    USE SIGNAL ;
    SHAPE ABUTMENT ;
    PORT
      LAYER met3 ;
      RECT 0.000 142.650 0.900 142.950 ;
    END
  END rw0_wd_in[5]
  PIN rw0_wd_in[6]
    DIRECTION INPUT ;
    USE SIGNAL ;
    SHAPE ABUTMENT ;
    PORT
      LAYER met3 ;
      RECT 0.000 145.370 0.900 145.670 ;
    END
  END rw0_wd_in[6]
  PIN rw0_wd_in[7]
    DIRECTION INPUT ;
    USE SIGNAL ;
    SHAPE ABUTMENT ;
    PORT
      LAYER met3 ;
      RECT 0.000 148.090 0.900 148.390 ;
    END
  END rw0_wd_in[7]
  PIN rw0_wd_in[8]
    DIRECTION INPUT ;
    USE SIGNAL ;
    SHAPE ABUTMENT ;
    PORT
      LAYER met3 ;
      RECT 0.000 150.810 0.900 151.110 ;
    END
  END rw0_wd_in[8]
  PIN rw0_wd_in[9]
    DIRECTION INPUT ;
    USE SIGNAL ;
    SHAPE ABUTMENT ;
    PORT
      LAYER met3 ;
      RECT 0.000 153.530 0.900 153.830 ;
    END
  END rw0_wd_in[9]
  PIN rw0_wd_in[10]
    DIRECTION INPUT ;
    USE SIGNAL ;
    SHAPE ABUTMENT ;
    PORT
      LAYER met3 ;
      RECT 0.000 156.250 0.900 156.550 ;
    END
  END rw0_wd_in[10]
  PIN rw0_wd_in[11]
    DIRECTION INPUT ;
    USE SIGNAL ;
    SHAPE ABUTMENT ;
    PORT
      LAYER met3 ;
      RECT 0.000 158.970 0.900 159.270 ;
    END
  END rw0_wd_in[11]
  PIN rw0_wd_in[12]
    DIRECTION INPUT ;
    USE SIGNAL ;
    SHAPE ABUTMENT ;
    PORT
      LAYER met3 ;
      RECT 0.000 161.690 0.900 161.990 ;
    END
  END rw0_wd_in[12]
  PIN rw0_wd_in[13]
    DIRECTION INPUT ;
    USE SIGNAL ;
    SHAPE ABUTMENT ;
    PORT
      LAYER met3 ;
      RECT 0.000 164.410 0.900 164.710 ;
    END
  END rw0_wd_in[13]
  PIN rw0_wd_in[14]
    DIRECTION INPUT ;
    USE SIGNAL ;
    SHAPE ABUTMENT ;
    PORT
      LAYER met3 ;
      RECT 0.000 167.130 0.900 167.430 ;
    END
  END rw0_wd_in[14]
  PIN rw0_wd_in[15]
    DIRECTION INPUT ;
    USE SIGNAL ;
    SHAPE ABUTMENT ;
    PORT
      LAYER met3 ;
      RECT 0.000 169.850 0.900 170.150 ;
    END
  END rw0_wd_in[15]
  PIN rw0_wd_in[16]
    DIRECTION INPUT ;
    USE SIGNAL ;
    SHAPE ABUTMENT ;
    PORT
      LAYER met3 ;
      RECT 0.000 172.570 0.900 172.870 ;
    END
  END rw0_wd_in[16]
  PIN rw0_wd_in[17]
    DIRECTION INPUT ;
    USE SIGNAL ;
    SHAPE ABUTMENT ;
    PORT
      LAYER met3 ;
      RECT 0.000 175.290 0.900 175.590 ;
    END
  END rw0_wd_in[17]
  PIN rw0_wd_in[18]
    DIRECTION INPUT ;
    USE SIGNAL ;
    SHAPE ABUTMENT ;
    PORT
      LAYER met3 ;
      RECT 0.000 178.010 0.900 178.310 ;
    END
  END rw0_wd_in[18]
  PIN rw0_wd_in[19]
    DIRECTION INPUT ;
    USE SIGNAL ;
    SHAPE ABUTMENT ;
    PORT
      LAYER met3 ;
      RECT 0.000 180.730 0.900 181.030 ;
    END
  END rw0_wd_in[19]
  PIN rw0_wd_in[20]
    DIRECTION INPUT ;
    USE SIGNAL ;
    SHAPE ABUTMENT ;
    PORT
      LAYER met3 ;
      RECT 0.000 183.450 0.900 183.750 ;
    END
  END rw0_wd_in[20]
  PIN rw0_wd_in[21]
    DIRECTION INPUT ;
    USE SIGNAL ;
    SHAPE ABUTMENT ;
    PORT
      LAYER met3 ;
      RECT 0.000 186.170 0.900 186.470 ;
    END
  END rw0_wd_in[21]
  PIN rw0_wd_in[22]
    DIRECTION INPUT ;
    USE SIGNAL ;
    SHAPE ABUTMENT ;
    PORT
      LAYER met3 ;
      RECT 0.000 188.890 0.900 189.190 ;
    END
  END rw0_wd_in[22]
  PIN rw0_wd_in[23]
    DIRECTION INPUT ;
    USE SIGNAL ;
    SHAPE ABUTMENT ;
    PORT
      LAYER met3 ;
      RECT 0.000 191.610 0.900 191.910 ;
    END
  END rw0_wd_in[23]
  PIN rw0_wd_in[24]
    DIRECTION INPUT ;
    USE SIGNAL ;
    SHAPE ABUTMENT ;
    PORT
      LAYER met3 ;
      RECT 0.000 194.330 0.900 194.630 ;
    END
  END rw0_wd_in[24]
  PIN rw0_wd_in[25]
    DIRECTION INPUT ;
    USE SIGNAL ;
    SHAPE ABUTMENT ;
    PORT
      LAYER met3 ;
      RECT 0.000 197.050 0.900 197.350 ;
    END
  END rw0_wd_in[25]
  PIN rw0_wd_in[26]
    DIRECTION INPUT ;
    USE SIGNAL ;
    SHAPE ABUTMENT ;
    PORT
      LAYER met3 ;
      RECT 0.000 199.770 0.900 200.070 ;
    END
  END rw0_wd_in[26]
  PIN rw0_wd_in[27]
    DIRECTION INPUT ;
    USE SIGNAL ;
    SHAPE ABUTMENT ;
    PORT
      LAYER met3 ;
      RECT 0.000 202.490 0.900 202.790 ;
    END
  END rw0_wd_in[27]
  PIN rw0_wd_in[28]
    DIRECTION INPUT ;
    USE SIGNAL ;
    SHAPE ABUTMENT ;
    PORT
      LAYER met3 ;
      RECT 0.000 205.210 0.900 205.510 ;
    END
  END rw0_wd_in[28]
  PIN rw0_wd_in[29]
    DIRECTION INPUT ;
    USE SIGNAL ;
    SHAPE ABUTMENT ;
    PORT
      LAYER met3 ;
      RECT 0.000 207.930 0.900 208.230 ;
    END
  END rw0_wd_in[29]
  PIN rw0_wd_in[30]
    DIRECTION INPUT ;
    USE SIGNAL ;
    SHAPE ABUTMENT ;
    PORT
      LAYER met3 ;
      RECT 0.000 210.650 0.900 210.950 ;
    END
  END rw0_wd_in[30]
  PIN rw0_wd_in[31]
    DIRECTION INPUT ;
    USE SIGNAL ;
    SHAPE ABUTMENT ;
    PORT
      LAYER met3 ;
      RECT 0.000 213.370 0.900 213.670 ;
    END
  END rw0_wd_in[31]
  PIN rw0_wd_in[32]
    DIRECTION INPUT ;
    USE SIGNAL ;
    SHAPE ABUTMENT ;
    PORT
      LAYER met3 ;
      RECT 0.000 216.090 0.900 216.390 ;
    END
  END rw0_wd_in[32]
  PIN rw0_wd_in[33]
    DIRECTION INPUT ;
    USE SIGNAL ;
    SHAPE ABUTMENT ;
    PORT
      LAYER met3 ;
      RECT 0.000 218.810 0.900 219.110 ;
    END
  END rw0_wd_in[33]
  PIN rw0_wd_in[34]
    DIRECTION INPUT ;
    USE SIGNAL ;
    SHAPE ABUTMENT ;
    PORT
      LAYER met3 ;
      RECT 0.000 221.530 0.900 221.830 ;
    END
  END rw0_wd_in[34]
  PIN rw0_wd_in[35]
    DIRECTION INPUT ;
    USE SIGNAL ;
    SHAPE ABUTMENT ;
    PORT
      LAYER met3 ;
      RECT 0.000 224.250 0.900 224.550 ;
    END
  END rw0_wd_in[35]
  PIN rw0_wd_in[36]
    DIRECTION INPUT ;
    USE SIGNAL ;
    SHAPE ABUTMENT ;
    PORT
      LAYER met3 ;
      RECT 0.000 226.970 0.900 227.270 ;
    END
  END rw0_wd_in[36]
  PIN rw0_wd_in[37]
    DIRECTION INPUT ;
    USE SIGNAL ;
    SHAPE ABUTMENT ;
    PORT
      LAYER met3 ;
      RECT 0.000 229.690 0.900 229.990 ;
    END
  END rw0_wd_in[37]
  PIN rw0_wd_in[38]
    DIRECTION INPUT ;
    USE SIGNAL ;
    SHAPE ABUTMENT ;
    PORT
      LAYER met3 ;
      RECT 0.000 232.410 0.900 232.710 ;
    END
  END rw0_wd_in[38]
  PIN rw0_wd_in[39]
    DIRECTION INPUT ;
    USE SIGNAL ;
    SHAPE ABUTMENT ;
    PORT
      LAYER met3 ;
      RECT 0.000 235.130 0.900 235.430 ;
    END
  END rw0_wd_in[39]
  PIN rw0_wd_in[40]
    DIRECTION INPUT ;
    USE SIGNAL ;
    SHAPE ABUTMENT ;
    PORT
      LAYER met3 ;
      RECT 0.000 237.850 0.900 238.150 ;
    END
  END rw0_wd_in[40]
  PIN rw0_wd_in[41]
    DIRECTION INPUT ;
    USE SIGNAL ;
    SHAPE ABUTMENT ;
    PORT
      LAYER met3 ;
      RECT 0.000 240.570 0.900 240.870 ;
    END
  END rw0_wd_in[41]
  PIN rw0_wd_in[42]
    DIRECTION INPUT ;
    USE SIGNAL ;
    SHAPE ABUTMENT ;
    PORT
      LAYER met3 ;
      RECT 0.000 243.290 0.900 243.590 ;
    END
  END rw0_wd_in[42]
  PIN rw0_wd_in[43]
    DIRECTION INPUT ;
    USE SIGNAL ;
    SHAPE ABUTMENT ;
    PORT
      LAYER met3 ;
      RECT 0.000 246.010 0.900 246.310 ;
    END
  END rw0_wd_in[43]
  PIN rw0_wd_in[44]
    DIRECTION INPUT ;
    USE SIGNAL ;
    SHAPE ABUTMENT ;
    PORT
      LAYER met3 ;
      RECT 0.000 248.730 0.900 249.030 ;
    END
  END rw0_wd_in[44]
  PIN rw0_wd_in[45]
    DIRECTION INPUT ;
    USE SIGNAL ;
    SHAPE ABUTMENT ;
    PORT
      LAYER met3 ;
      RECT 0.000 251.450 0.900 251.750 ;
    END
  END rw0_wd_in[45]
  PIN rw0_wd_in[46]
    DIRECTION INPUT ;
    USE SIGNAL ;
    SHAPE ABUTMENT ;
    PORT
      LAYER met3 ;
      RECT 513.840 129.050 514.740 129.350 ;
    END
  END rw0_wd_in[46]
  PIN rw0_wd_in[47]
    DIRECTION INPUT ;
    USE SIGNAL ;
    SHAPE ABUTMENT ;
    PORT
      LAYER met3 ;
      RECT 513.840 131.770 514.740 132.070 ;
    END
  END rw0_wd_in[47]
  PIN rw0_wd_in[48]
    DIRECTION INPUT ;
    USE SIGNAL ;
    SHAPE ABUTMENT ;
    PORT
      LAYER met3 ;
      RECT 513.840 134.490 514.740 134.790 ;
    END
  END rw0_wd_in[48]
  PIN rw0_wd_in[49]
    DIRECTION INPUT ;
    USE SIGNAL ;
    SHAPE ABUTMENT ;
    PORT
      LAYER met3 ;
      RECT 513.840 137.210 514.740 137.510 ;
    END
  END rw0_wd_in[49]
  PIN rw0_wd_in[50]
    DIRECTION INPUT ;
    USE SIGNAL ;
    SHAPE ABUTMENT ;
    PORT
      LAYER met3 ;
      RECT 513.840 139.930 514.740 140.230 ;
    END
  END rw0_wd_in[50]
  PIN rw0_wd_in[51]
    DIRECTION INPUT ;
    USE SIGNAL ;
    SHAPE ABUTMENT ;
    PORT
      LAYER met3 ;
      RECT 513.840 142.650 514.740 142.950 ;
    END
  END rw0_wd_in[51]
  PIN rw0_wd_in[52]
    DIRECTION INPUT ;
    USE SIGNAL ;
    SHAPE ABUTMENT ;
    PORT
      LAYER met3 ;
      RECT 513.840 145.370 514.740 145.670 ;
    END
  END rw0_wd_in[52]
  PIN rw0_wd_in[53]
    DIRECTION INPUT ;
    USE SIGNAL ;
    SHAPE ABUTMENT ;
    PORT
      LAYER met3 ;
      RECT 513.840 148.090 514.740 148.390 ;
    END
  END rw0_wd_in[53]
  PIN rw0_wd_in[54]
    DIRECTION INPUT ;
    USE SIGNAL ;
    SHAPE ABUTMENT ;
    PORT
      LAYER met3 ;
      RECT 513.840 150.810 514.740 151.110 ;
    END
  END rw0_wd_in[54]
  PIN rw0_wd_in[55]
    DIRECTION INPUT ;
    USE SIGNAL ;
    SHAPE ABUTMENT ;
    PORT
      LAYER met3 ;
      RECT 513.840 153.530 514.740 153.830 ;
    END
  END rw0_wd_in[55]
  PIN rw0_wd_in[56]
    DIRECTION INPUT ;
    USE SIGNAL ;
    SHAPE ABUTMENT ;
    PORT
      LAYER met3 ;
      RECT 513.840 156.250 514.740 156.550 ;
    END
  END rw0_wd_in[56]
  PIN rw0_wd_in[57]
    DIRECTION INPUT ;
    USE SIGNAL ;
    SHAPE ABUTMENT ;
    PORT
      LAYER met3 ;
      RECT 513.840 158.970 514.740 159.270 ;
    END
  END rw0_wd_in[57]
  PIN rw0_wd_in[58]
    DIRECTION INPUT ;
    USE SIGNAL ;
    SHAPE ABUTMENT ;
    PORT
      LAYER met3 ;
      RECT 513.840 161.690 514.740 161.990 ;
    END
  END rw0_wd_in[58]
  PIN rw0_wd_in[59]
    DIRECTION INPUT ;
    USE SIGNAL ;
    SHAPE ABUTMENT ;
    PORT
      LAYER met3 ;
      RECT 513.840 164.410 514.740 164.710 ;
    END
  END rw0_wd_in[59]
  PIN rw0_wd_in[60]
    DIRECTION INPUT ;
    USE SIGNAL ;
    SHAPE ABUTMENT ;
    PORT
      LAYER met3 ;
      RECT 513.840 167.130 514.740 167.430 ;
    END
  END rw0_wd_in[60]
  PIN rw0_wd_in[61]
    DIRECTION INPUT ;
    USE SIGNAL ;
    SHAPE ABUTMENT ;
    PORT
      LAYER met3 ;
      RECT 513.840 169.850 514.740 170.150 ;
    END
  END rw0_wd_in[61]
  PIN rw0_wd_in[62]
    DIRECTION INPUT ;
    USE SIGNAL ;
    SHAPE ABUTMENT ;
    PORT
      LAYER met3 ;
      RECT 513.840 172.570 514.740 172.870 ;
    END
  END rw0_wd_in[62]
  PIN rw0_wd_in[63]
    DIRECTION INPUT ;
    USE SIGNAL ;
    SHAPE ABUTMENT ;
    PORT
      LAYER met3 ;
      RECT 513.840 175.290 514.740 175.590 ;
    END
  END rw0_wd_in[63]
  PIN rw0_wd_in[64]
    DIRECTION INPUT ;
    USE SIGNAL ;
    SHAPE ABUTMENT ;
    PORT
      LAYER met3 ;
      RECT 513.840 178.010 514.740 178.310 ;
    END
  END rw0_wd_in[64]
  PIN rw0_wd_in[65]
    DIRECTION INPUT ;
    USE SIGNAL ;
    SHAPE ABUTMENT ;
    PORT
      LAYER met3 ;
      RECT 513.840 180.730 514.740 181.030 ;
    END
  END rw0_wd_in[65]
  PIN rw0_wd_in[66]
    DIRECTION INPUT ;
    USE SIGNAL ;
    SHAPE ABUTMENT ;
    PORT
      LAYER met3 ;
      RECT 513.840 183.450 514.740 183.750 ;
    END
  END rw0_wd_in[66]
  PIN rw0_wd_in[67]
    DIRECTION INPUT ;
    USE SIGNAL ;
    SHAPE ABUTMENT ;
    PORT
      LAYER met3 ;
      RECT 513.840 186.170 514.740 186.470 ;
    END
  END rw0_wd_in[67]
  PIN rw0_wd_in[68]
    DIRECTION INPUT ;
    USE SIGNAL ;
    SHAPE ABUTMENT ;
    PORT
      LAYER met3 ;
      RECT 513.840 188.890 514.740 189.190 ;
    END
  END rw0_wd_in[68]
  PIN rw0_wd_in[69]
    DIRECTION INPUT ;
    USE SIGNAL ;
    SHAPE ABUTMENT ;
    PORT
      LAYER met3 ;
      RECT 513.840 191.610 514.740 191.910 ;
    END
  END rw0_wd_in[69]
  PIN rw0_wd_in[70]
    DIRECTION INPUT ;
    USE SIGNAL ;
    SHAPE ABUTMENT ;
    PORT
      LAYER met3 ;
      RECT 513.840 194.330 514.740 194.630 ;
    END
  END rw0_wd_in[70]
  PIN rw0_wd_in[71]
    DIRECTION INPUT ;
    USE SIGNAL ;
    SHAPE ABUTMENT ;
    PORT
      LAYER met3 ;
      RECT 513.840 197.050 514.740 197.350 ;
    END
  END rw0_wd_in[71]
  PIN rw0_wd_in[72]
    DIRECTION INPUT ;
    USE SIGNAL ;
    SHAPE ABUTMENT ;
    PORT
      LAYER met3 ;
      RECT 513.840 199.770 514.740 200.070 ;
    END
  END rw0_wd_in[72]
  PIN rw0_wd_in[73]
    DIRECTION INPUT ;
    USE SIGNAL ;
    SHAPE ABUTMENT ;
    PORT
      LAYER met3 ;
      RECT 513.840 202.490 514.740 202.790 ;
    END
  END rw0_wd_in[73]
  PIN rw0_wd_in[74]
    DIRECTION INPUT ;
    USE SIGNAL ;
    SHAPE ABUTMENT ;
    PORT
      LAYER met3 ;
      RECT 513.840 205.210 514.740 205.510 ;
    END
  END rw0_wd_in[74]
  PIN rw0_wd_in[75]
    DIRECTION INPUT ;
    USE SIGNAL ;
    SHAPE ABUTMENT ;
    PORT
      LAYER met3 ;
      RECT 513.840 207.930 514.740 208.230 ;
    END
  END rw0_wd_in[75]
  PIN rw0_wd_in[76]
    DIRECTION INPUT ;
    USE SIGNAL ;
    SHAPE ABUTMENT ;
    PORT
      LAYER met3 ;
      RECT 513.840 210.650 514.740 210.950 ;
    END
  END rw0_wd_in[76]
  PIN rw0_wd_in[77]
    DIRECTION INPUT ;
    USE SIGNAL ;
    SHAPE ABUTMENT ;
    PORT
      LAYER met3 ;
      RECT 513.840 213.370 514.740 213.670 ;
    END
  END rw0_wd_in[77]
  PIN rw0_wd_in[78]
    DIRECTION INPUT ;
    USE SIGNAL ;
    SHAPE ABUTMENT ;
    PORT
      LAYER met3 ;
      RECT 513.840 216.090 514.740 216.390 ;
    END
  END rw0_wd_in[78]
  PIN rw0_wd_in[79]
    DIRECTION INPUT ;
    USE SIGNAL ;
    SHAPE ABUTMENT ;
    PORT
      LAYER met3 ;
      RECT 513.840 218.810 514.740 219.110 ;
    END
  END rw0_wd_in[79]
  PIN rw0_wd_in[80]
    DIRECTION INPUT ;
    USE SIGNAL ;
    SHAPE ABUTMENT ;
    PORT
      LAYER met3 ;
      RECT 513.840 221.530 514.740 221.830 ;
    END
  END rw0_wd_in[80]
  PIN rw0_wd_in[81]
    DIRECTION INPUT ;
    USE SIGNAL ;
    SHAPE ABUTMENT ;
    PORT
      LAYER met3 ;
      RECT 513.840 224.250 514.740 224.550 ;
    END
  END rw0_wd_in[81]
  PIN rw0_wd_in[82]
    DIRECTION INPUT ;
    USE SIGNAL ;
    SHAPE ABUTMENT ;
    PORT
      LAYER met3 ;
      RECT 513.840 226.970 514.740 227.270 ;
    END
  END rw0_wd_in[82]
  PIN rw0_wd_in[83]
    DIRECTION INPUT ;
    USE SIGNAL ;
    SHAPE ABUTMENT ;
    PORT
      LAYER met3 ;
      RECT 513.840 229.690 514.740 229.990 ;
    END
  END rw0_wd_in[83]
  PIN rw0_wd_in[84]
    DIRECTION INPUT ;
    USE SIGNAL ;
    SHAPE ABUTMENT ;
    PORT
      LAYER met3 ;
      RECT 513.840 232.410 514.740 232.710 ;
    END
  END rw0_wd_in[84]
  PIN rw0_wd_in[85]
    DIRECTION INPUT ;
    USE SIGNAL ;
    SHAPE ABUTMENT ;
    PORT
      LAYER met3 ;
      RECT 513.840 235.130 514.740 235.430 ;
    END
  END rw0_wd_in[85]
  PIN rw0_wd_in[86]
    DIRECTION INPUT ;
    USE SIGNAL ;
    SHAPE ABUTMENT ;
    PORT
      LAYER met3 ;
      RECT 513.840 237.850 514.740 238.150 ;
    END
  END rw0_wd_in[86]
  PIN rw0_wd_in[87]
    DIRECTION INPUT ;
    USE SIGNAL ;
    SHAPE ABUTMENT ;
    PORT
      LAYER met3 ;
      RECT 513.840 240.570 514.740 240.870 ;
    END
  END rw0_wd_in[87]
  PIN rw0_wd_in[88]
    DIRECTION INPUT ;
    USE SIGNAL ;
    SHAPE ABUTMENT ;
    PORT
      LAYER met3 ;
      RECT 513.840 243.290 514.740 243.590 ;
    END
  END rw0_wd_in[88]
  PIN rw0_wd_in[89]
    DIRECTION INPUT ;
    USE SIGNAL ;
    SHAPE ABUTMENT ;
    PORT
      LAYER met3 ;
      RECT 513.840 246.010 514.740 246.310 ;
    END
  END rw0_wd_in[89]
  PIN rw0_wd_in[90]
    DIRECTION INPUT ;
    USE SIGNAL ;
    SHAPE ABUTMENT ;
    PORT
      LAYER met3 ;
      RECT 513.840 248.730 514.740 249.030 ;
    END
  END rw0_wd_in[90]
  PIN rw0_wd_in[91]
    DIRECTION INPUT ;
    USE SIGNAL ;
    SHAPE ABUTMENT ;
    PORT
      LAYER met3 ;
      RECT 513.840 251.450 514.740 251.750 ;
    END
  END rw0_wd_in[91]
  PIN rw0_wd_in[92]
    DIRECTION INPUT ;
    USE SIGNAL ;
    SHAPE ABUTMENT ;
    PORT
      LAYER met2 ;
      RECT 2.690 0.000 2.830 0.420 ;
    END
  END rw0_wd_in[92]
  PIN rw0_wd_in[93]
    DIRECTION INPUT ;
    USE SIGNAL ;
    SHAPE ABUTMENT ;
    PORT
      LAYER met2 ;
      RECT 5.450 0.000 5.590 0.420 ;
    END
  END rw0_wd_in[93]
  PIN rw0_wd_in[94]
    DIRECTION INPUT ;
    USE SIGNAL ;
    SHAPE ABUTMENT ;
    PORT
      LAYER met2 ;
      RECT 8.210 0.000 8.350 0.420 ;
    END
  END rw0_wd_in[94]
  PIN rw0_wd_in[95]
    DIRECTION INPUT ;
    USE SIGNAL ;
    SHAPE ABUTMENT ;
    PORT
      LAYER met2 ;
      RECT 10.970 0.000 11.110 0.420 ;
    END
  END rw0_wd_in[95]
  PIN rw0_wd_in[96]
    DIRECTION INPUT ;
    USE SIGNAL ;
    SHAPE ABUTMENT ;
    PORT
      LAYER met2 ;
      RECT 13.730 0.000 13.870 0.420 ;
    END
  END rw0_wd_in[96]
  PIN rw0_wd_in[97]
    DIRECTION INPUT ;
    USE SIGNAL ;
    SHAPE ABUTMENT ;
    PORT
      LAYER met2 ;
      RECT 16.490 0.000 16.630 0.420 ;
    END
  END rw0_wd_in[97]
  PIN rw0_wd_in[98]
    DIRECTION INPUT ;
    USE SIGNAL ;
    SHAPE ABUTMENT ;
    PORT
      LAYER met2 ;
      RECT 19.250 0.000 19.390 0.420 ;
    END
  END rw0_wd_in[98]
  PIN rw0_wd_in[99]
    DIRECTION INPUT ;
    USE SIGNAL ;
    SHAPE ABUTMENT ;
    PORT
      LAYER met2 ;
      RECT 22.010 0.000 22.150 0.420 ;
    END
  END rw0_wd_in[99]
  PIN rw0_wd_in[100]
    DIRECTION INPUT ;
    USE SIGNAL ;
    SHAPE ABUTMENT ;
    PORT
      LAYER met2 ;
      RECT 24.770 0.000 24.910 0.420 ;
    END
  END rw0_wd_in[100]
  PIN rw0_wd_in[101]
    DIRECTION INPUT ;
    USE SIGNAL ;
    SHAPE ABUTMENT ;
    PORT
      LAYER met2 ;
      RECT 27.530 0.000 27.670 0.420 ;
    END
  END rw0_wd_in[101]
  PIN rw0_wd_in[102]
    DIRECTION INPUT ;
    USE SIGNAL ;
    SHAPE ABUTMENT ;
    PORT
      LAYER met2 ;
      RECT 30.290 0.000 30.430 0.420 ;
    END
  END rw0_wd_in[102]
  PIN rw0_wd_in[103]
    DIRECTION INPUT ;
    USE SIGNAL ;
    SHAPE ABUTMENT ;
    PORT
      LAYER met2 ;
      RECT 33.050 0.000 33.190 0.420 ;
    END
  END rw0_wd_in[103]
  PIN rw0_wd_in[104]
    DIRECTION INPUT ;
    USE SIGNAL ;
    SHAPE ABUTMENT ;
    PORT
      LAYER met2 ;
      RECT 35.810 0.000 35.950 0.420 ;
    END
  END rw0_wd_in[104]
  PIN rw0_wd_in[105]
    DIRECTION INPUT ;
    USE SIGNAL ;
    SHAPE ABUTMENT ;
    PORT
      LAYER met2 ;
      RECT 38.570 0.000 38.710 0.420 ;
    END
  END rw0_wd_in[105]
  PIN rw0_wd_in[106]
    DIRECTION INPUT ;
    USE SIGNAL ;
    SHAPE ABUTMENT ;
    PORT
      LAYER met2 ;
      RECT 41.330 0.000 41.470 0.420 ;
    END
  END rw0_wd_in[106]
  PIN rw0_wd_in[107]
    DIRECTION INPUT ;
    USE SIGNAL ;
    SHAPE ABUTMENT ;
    PORT
      LAYER met2 ;
      RECT 44.090 0.000 44.230 0.420 ;
    END
  END rw0_wd_in[107]
  PIN rw0_wd_in[108]
    DIRECTION INPUT ;
    USE SIGNAL ;
    SHAPE ABUTMENT ;
    PORT
      LAYER met2 ;
      RECT 46.850 0.000 46.990 0.420 ;
    END
  END rw0_wd_in[108]
  PIN rw0_wd_in[109]
    DIRECTION INPUT ;
    USE SIGNAL ;
    SHAPE ABUTMENT ;
    PORT
      LAYER met2 ;
      RECT 49.610 0.000 49.750 0.420 ;
    END
  END rw0_wd_in[109]
  PIN rw0_wd_in[110]
    DIRECTION INPUT ;
    USE SIGNAL ;
    SHAPE ABUTMENT ;
    PORT
      LAYER met2 ;
      RECT 52.370 0.000 52.510 0.420 ;
    END
  END rw0_wd_in[110]
  PIN rw0_wd_in[111]
    DIRECTION INPUT ;
    USE SIGNAL ;
    SHAPE ABUTMENT ;
    PORT
      LAYER met2 ;
      RECT 55.130 0.000 55.270 0.420 ;
    END
  END rw0_wd_in[111]
  PIN rw0_wd_in[112]
    DIRECTION INPUT ;
    USE SIGNAL ;
    SHAPE ABUTMENT ;
    PORT
      LAYER met2 ;
      RECT 57.890 0.000 58.030 0.420 ;
    END
  END rw0_wd_in[112]
  PIN rw0_wd_in[113]
    DIRECTION INPUT ;
    USE SIGNAL ;
    SHAPE ABUTMENT ;
    PORT
      LAYER met2 ;
      RECT 60.650 0.000 60.790 0.420 ;
    END
  END rw0_wd_in[113]
  PIN rw0_wd_in[114]
    DIRECTION INPUT ;
    USE SIGNAL ;
    SHAPE ABUTMENT ;
    PORT
      LAYER met2 ;
      RECT 63.410 0.000 63.550 0.420 ;
    END
  END rw0_wd_in[114]
  PIN rw0_wd_in[115]
    DIRECTION INPUT ;
    USE SIGNAL ;
    SHAPE ABUTMENT ;
    PORT
      LAYER met2 ;
      RECT 66.170 0.000 66.310 0.420 ;
    END
  END rw0_wd_in[115]
  PIN rw0_wd_in[116]
    DIRECTION INPUT ;
    USE SIGNAL ;
    SHAPE ABUTMENT ;
    PORT
      LAYER met2 ;
      RECT 68.930 0.000 69.070 0.420 ;
    END
  END rw0_wd_in[116]
  PIN rw0_wd_in[117]
    DIRECTION INPUT ;
    USE SIGNAL ;
    SHAPE ABUTMENT ;
    PORT
      LAYER met2 ;
      RECT 71.690 0.000 71.830 0.420 ;
    END
  END rw0_wd_in[117]
  PIN rw0_wd_in[118]
    DIRECTION INPUT ;
    USE SIGNAL ;
    SHAPE ABUTMENT ;
    PORT
      LAYER met2 ;
      RECT 74.450 0.000 74.590 0.420 ;
    END
  END rw0_wd_in[118]
  PIN rw0_wd_in[119]
    DIRECTION INPUT ;
    USE SIGNAL ;
    SHAPE ABUTMENT ;
    PORT
      LAYER met2 ;
      RECT 77.210 0.000 77.350 0.420 ;
    END
  END rw0_wd_in[119]
  PIN rw0_wd_in[120]
    DIRECTION INPUT ;
    USE SIGNAL ;
    SHAPE ABUTMENT ;
    PORT
      LAYER met2 ;
      RECT 79.970 0.000 80.110 0.420 ;
    END
  END rw0_wd_in[120]
  PIN rw0_wd_in[121]
    DIRECTION INPUT ;
    USE SIGNAL ;
    SHAPE ABUTMENT ;
    PORT
      LAYER met2 ;
      RECT 82.730 0.000 82.870 0.420 ;
    END
  END rw0_wd_in[121]
  PIN rw0_wd_in[122]
    DIRECTION INPUT ;
    USE SIGNAL ;
    SHAPE ABUTMENT ;
    PORT
      LAYER met2 ;
      RECT 85.490 0.000 85.630 0.420 ;
    END
  END rw0_wd_in[122]
  PIN rw0_wd_in[123]
    DIRECTION INPUT ;
    USE SIGNAL ;
    SHAPE ABUTMENT ;
    PORT
      LAYER met2 ;
      RECT 88.250 0.000 88.390 0.420 ;
    END
  END rw0_wd_in[123]
  PIN rw0_wd_in[124]
    DIRECTION INPUT ;
    USE SIGNAL ;
    SHAPE ABUTMENT ;
    PORT
      LAYER met2 ;
      RECT 91.010 0.000 91.150 0.420 ;
    END
  END rw0_wd_in[124]
  PIN rw0_wd_in[125]
    DIRECTION INPUT ;
    USE SIGNAL ;
    SHAPE ABUTMENT ;
    PORT
      LAYER met2 ;
      RECT 93.770 0.000 93.910 0.420 ;
    END
  END rw0_wd_in[125]
  PIN rw0_wd_in[126]
    DIRECTION INPUT ;
    USE SIGNAL ;
    SHAPE ABUTMENT ;
    PORT
      LAYER met2 ;
      RECT 96.530 0.000 96.670 0.420 ;
    END
  END rw0_wd_in[126]
  PIN rw0_wd_in[127]
    DIRECTION INPUT ;
    USE SIGNAL ;
    SHAPE ABUTMENT ;
    PORT
      LAYER met2 ;
      RECT 99.290 0.000 99.430 0.420 ;
    END
  END rw0_wd_in[127]
  PIN rw0_wd_in[128]
    DIRECTION INPUT ;
    USE SIGNAL ;
    SHAPE ABUTMENT ;
    PORT
      LAYER met2 ;
      RECT 102.050 0.000 102.190 0.420 ;
    END
  END rw0_wd_in[128]
  PIN rw0_wd_in[129]
    DIRECTION INPUT ;
    USE SIGNAL ;
    SHAPE ABUTMENT ;
    PORT
      LAYER met2 ;
      RECT 104.810 0.000 104.950 0.420 ;
    END
  END rw0_wd_in[129]
  PIN rw0_wd_in[130]
    DIRECTION INPUT ;
    USE SIGNAL ;
    SHAPE ABUTMENT ;
    PORT
      LAYER met2 ;
      RECT 107.570 0.000 107.710 0.420 ;
    END
  END rw0_wd_in[130]
  PIN rw0_wd_in[131]
    DIRECTION INPUT ;
    USE SIGNAL ;
    SHAPE ABUTMENT ;
    PORT
      LAYER met2 ;
      RECT 110.330 0.000 110.470 0.420 ;
    END
  END rw0_wd_in[131]
  PIN rw0_wd_in[132]
    DIRECTION INPUT ;
    USE SIGNAL ;
    SHAPE ABUTMENT ;
    PORT
      LAYER met2 ;
      RECT 113.090 0.000 113.230 0.420 ;
    END
  END rw0_wd_in[132]
  PIN rw0_wd_in[133]
    DIRECTION INPUT ;
    USE SIGNAL ;
    SHAPE ABUTMENT ;
    PORT
      LAYER met2 ;
      RECT 115.850 0.000 115.990 0.420 ;
    END
  END rw0_wd_in[133]
  PIN rw0_wd_in[134]
    DIRECTION INPUT ;
    USE SIGNAL ;
    SHAPE ABUTMENT ;
    PORT
      LAYER met2 ;
      RECT 118.610 0.000 118.750 0.420 ;
    END
  END rw0_wd_in[134]
  PIN rw0_wd_in[135]
    DIRECTION INPUT ;
    USE SIGNAL ;
    SHAPE ABUTMENT ;
    PORT
      LAYER met2 ;
      RECT 121.370 0.000 121.510 0.420 ;
    END
  END rw0_wd_in[135]
  PIN rw0_wd_in[136]
    DIRECTION INPUT ;
    USE SIGNAL ;
    SHAPE ABUTMENT ;
    PORT
      LAYER met2 ;
      RECT 124.130 0.000 124.270 0.420 ;
    END
  END rw0_wd_in[136]
  PIN rw0_wd_in[137]
    DIRECTION INPUT ;
    USE SIGNAL ;
    SHAPE ABUTMENT ;
    PORT
      LAYER met2 ;
      RECT 126.890 0.000 127.030 0.420 ;
    END
  END rw0_wd_in[137]
  PIN rw0_wd_in[138]
    DIRECTION INPUT ;
    USE SIGNAL ;
    SHAPE ABUTMENT ;
    PORT
      LAYER met2 ;
      RECT 129.650 0.000 129.790 0.420 ;
    END
  END rw0_wd_in[138]
  PIN rw0_wd_in[139]
    DIRECTION INPUT ;
    USE SIGNAL ;
    SHAPE ABUTMENT ;
    PORT
      LAYER met2 ;
      RECT 132.410 0.000 132.550 0.420 ;
    END
  END rw0_wd_in[139]
  PIN rw0_wd_in[140]
    DIRECTION INPUT ;
    USE SIGNAL ;
    SHAPE ABUTMENT ;
    PORT
      LAYER met2 ;
      RECT 135.170 0.000 135.310 0.420 ;
    END
  END rw0_wd_in[140]
  PIN rw0_wd_in[141]
    DIRECTION INPUT ;
    USE SIGNAL ;
    SHAPE ABUTMENT ;
    PORT
      LAYER met2 ;
      RECT 137.930 0.000 138.070 0.420 ;
    END
  END rw0_wd_in[141]
  PIN rw0_wd_in[142]
    DIRECTION INPUT ;
    USE SIGNAL ;
    SHAPE ABUTMENT ;
    PORT
      LAYER met2 ;
      RECT 140.690 0.000 140.830 0.420 ;
    END
  END rw0_wd_in[142]
  PIN rw0_wd_in[143]
    DIRECTION INPUT ;
    USE SIGNAL ;
    SHAPE ABUTMENT ;
    PORT
      LAYER met2 ;
      RECT 143.450 0.000 143.590 0.420 ;
    END
  END rw0_wd_in[143]
  PIN rw0_wd_in[144]
    DIRECTION INPUT ;
    USE SIGNAL ;
    SHAPE ABUTMENT ;
    PORT
      LAYER met2 ;
      RECT 146.210 0.000 146.350 0.420 ;
    END
  END rw0_wd_in[144]
  PIN rw0_wd_in[145]
    DIRECTION INPUT ;
    USE SIGNAL ;
    SHAPE ABUTMENT ;
    PORT
      LAYER met2 ;
      RECT 148.970 0.000 149.110 0.420 ;
    END
  END rw0_wd_in[145]
  PIN rw0_wd_in[146]
    DIRECTION INPUT ;
    USE SIGNAL ;
    SHAPE ABUTMENT ;
    PORT
      LAYER met2 ;
      RECT 151.730 0.000 151.870 0.420 ;
    END
  END rw0_wd_in[146]
  PIN rw0_wd_in[147]
    DIRECTION INPUT ;
    USE SIGNAL ;
    SHAPE ABUTMENT ;
    PORT
      LAYER met2 ;
      RECT 154.490 0.000 154.630 0.420 ;
    END
  END rw0_wd_in[147]
  PIN rw0_wd_in[148]
    DIRECTION INPUT ;
    USE SIGNAL ;
    SHAPE ABUTMENT ;
    PORT
      LAYER met2 ;
      RECT 157.250 0.000 157.390 0.420 ;
    END
  END rw0_wd_in[148]
  PIN rw0_wd_in[149]
    DIRECTION INPUT ;
    USE SIGNAL ;
    SHAPE ABUTMENT ;
    PORT
      LAYER met2 ;
      RECT 160.010 0.000 160.150 0.420 ;
    END
  END rw0_wd_in[149]
  PIN rw0_wd_in[150]
    DIRECTION INPUT ;
    USE SIGNAL ;
    SHAPE ABUTMENT ;
    PORT
      LAYER met2 ;
      RECT 162.770 0.000 162.910 0.420 ;
    END
  END rw0_wd_in[150]
  PIN rw0_wd_in[151]
    DIRECTION INPUT ;
    USE SIGNAL ;
    SHAPE ABUTMENT ;
    PORT
      LAYER met2 ;
      RECT 165.530 0.000 165.670 0.420 ;
    END
  END rw0_wd_in[151]
  PIN rw0_wd_in[152]
    DIRECTION INPUT ;
    USE SIGNAL ;
    SHAPE ABUTMENT ;
    PORT
      LAYER met2 ;
      RECT 168.290 0.000 168.430 0.420 ;
    END
  END rw0_wd_in[152]
  PIN rw0_wd_in[153]
    DIRECTION INPUT ;
    USE SIGNAL ;
    SHAPE ABUTMENT ;
    PORT
      LAYER met2 ;
      RECT 171.050 0.000 171.190 0.420 ;
    END
  END rw0_wd_in[153]
  PIN rw0_wd_in[154]
    DIRECTION INPUT ;
    USE SIGNAL ;
    SHAPE ABUTMENT ;
    PORT
      LAYER met2 ;
      RECT 173.810 0.000 173.950 0.420 ;
    END
  END rw0_wd_in[154]
  PIN rw0_wd_in[155]
    DIRECTION INPUT ;
    USE SIGNAL ;
    SHAPE ABUTMENT ;
    PORT
      LAYER met2 ;
      RECT 176.570 0.000 176.710 0.420 ;
    END
  END rw0_wd_in[155]
  PIN rw0_wd_in[156]
    DIRECTION INPUT ;
    USE SIGNAL ;
    SHAPE ABUTMENT ;
    PORT
      LAYER met2 ;
      RECT 179.330 0.000 179.470 0.420 ;
    END
  END rw0_wd_in[156]
  PIN rw0_wd_in[157]
    DIRECTION INPUT ;
    USE SIGNAL ;
    SHAPE ABUTMENT ;
    PORT
      LAYER met2 ;
      RECT 182.090 0.000 182.230 0.420 ;
    END
  END rw0_wd_in[157]
  PIN rw0_wd_in[158]
    DIRECTION INPUT ;
    USE SIGNAL ;
    SHAPE ABUTMENT ;
    PORT
      LAYER met2 ;
      RECT 184.850 0.000 184.990 0.420 ;
    END
  END rw0_wd_in[158]
  PIN rw0_wd_in[159]
    DIRECTION INPUT ;
    USE SIGNAL ;
    SHAPE ABUTMENT ;
    PORT
      LAYER met2 ;
      RECT 187.610 0.000 187.750 0.420 ;
    END
  END rw0_wd_in[159]
  PIN rw0_wd_in[160]
    DIRECTION INPUT ;
    USE SIGNAL ;
    SHAPE ABUTMENT ;
    PORT
      LAYER met2 ;
      RECT 190.370 0.000 190.510 0.420 ;
    END
  END rw0_wd_in[160]
  PIN rw0_wd_in[161]
    DIRECTION INPUT ;
    USE SIGNAL ;
    SHAPE ABUTMENT ;
    PORT
      LAYER met2 ;
      RECT 193.130 0.000 193.270 0.420 ;
    END
  END rw0_wd_in[161]
  PIN rw0_wd_in[162]
    DIRECTION INPUT ;
    USE SIGNAL ;
    SHAPE ABUTMENT ;
    PORT
      LAYER met2 ;
      RECT 195.890 0.000 196.030 0.420 ;
    END
  END rw0_wd_in[162]
  PIN rw0_wd_in[163]
    DIRECTION INPUT ;
    USE SIGNAL ;
    SHAPE ABUTMENT ;
    PORT
      LAYER met2 ;
      RECT 198.650 0.000 198.790 0.420 ;
    END
  END rw0_wd_in[163]
  PIN rw0_wd_in[164]
    DIRECTION INPUT ;
    USE SIGNAL ;
    SHAPE ABUTMENT ;
    PORT
      LAYER met2 ;
      RECT 201.410 0.000 201.550 0.420 ;
    END
  END rw0_wd_in[164]
  PIN rw0_wd_in[165]
    DIRECTION INPUT ;
    USE SIGNAL ;
    SHAPE ABUTMENT ;
    PORT
      LAYER met2 ;
      RECT 204.170 0.000 204.310 0.420 ;
    END
  END rw0_wd_in[165]
  PIN rw0_wd_in[166]
    DIRECTION INPUT ;
    USE SIGNAL ;
    SHAPE ABUTMENT ;
    PORT
      LAYER met2 ;
      RECT 206.930 0.000 207.070 0.420 ;
    END
  END rw0_wd_in[166]
  PIN rw0_wd_in[167]
    DIRECTION INPUT ;
    USE SIGNAL ;
    SHAPE ABUTMENT ;
    PORT
      LAYER met2 ;
      RECT 209.690 0.000 209.830 0.420 ;
    END
  END rw0_wd_in[167]
  PIN rw0_wd_in[168]
    DIRECTION INPUT ;
    USE SIGNAL ;
    SHAPE ABUTMENT ;
    PORT
      LAYER met2 ;
      RECT 212.450 0.000 212.590 0.420 ;
    END
  END rw0_wd_in[168]
  PIN rw0_wd_in[169]
    DIRECTION INPUT ;
    USE SIGNAL ;
    SHAPE ABUTMENT ;
    PORT
      LAYER met2 ;
      RECT 215.210 0.000 215.350 0.420 ;
    END
  END rw0_wd_in[169]
  PIN rw0_wd_in[170]
    DIRECTION INPUT ;
    USE SIGNAL ;
    SHAPE ABUTMENT ;
    PORT
      LAYER met2 ;
      RECT 217.970 0.000 218.110 0.420 ;
    END
  END rw0_wd_in[170]
  PIN rw0_wd_in[171]
    DIRECTION INPUT ;
    USE SIGNAL ;
    SHAPE ABUTMENT ;
    PORT
      LAYER met2 ;
      RECT 220.730 0.000 220.870 0.420 ;
    END
  END rw0_wd_in[171]
  PIN rw0_wd_in[172]
    DIRECTION INPUT ;
    USE SIGNAL ;
    SHAPE ABUTMENT ;
    PORT
      LAYER met2 ;
      RECT 223.490 0.000 223.630 0.420 ;
    END
  END rw0_wd_in[172]
  PIN rw0_wd_in[173]
    DIRECTION INPUT ;
    USE SIGNAL ;
    SHAPE ABUTMENT ;
    PORT
      LAYER met2 ;
      RECT 226.250 0.000 226.390 0.420 ;
    END
  END rw0_wd_in[173]
  PIN rw0_wd_in[174]
    DIRECTION INPUT ;
    USE SIGNAL ;
    SHAPE ABUTMENT ;
    PORT
      LAYER met2 ;
      RECT 229.010 0.000 229.150 0.420 ;
    END
  END rw0_wd_in[174]
  PIN rw0_wd_in[175]
    DIRECTION INPUT ;
    USE SIGNAL ;
    SHAPE ABUTMENT ;
    PORT
      LAYER met2 ;
      RECT 231.770 0.000 231.910 0.420 ;
    END
  END rw0_wd_in[175]
  PIN rw0_wd_in[176]
    DIRECTION INPUT ;
    USE SIGNAL ;
    SHAPE ABUTMENT ;
    PORT
      LAYER met2 ;
      RECT 234.530 0.000 234.670 0.420 ;
    END
  END rw0_wd_in[176]
  PIN rw0_wd_in[177]
    DIRECTION INPUT ;
    USE SIGNAL ;
    SHAPE ABUTMENT ;
    PORT
      LAYER met2 ;
      RECT 237.290 0.000 237.430 0.420 ;
    END
  END rw0_wd_in[177]
  PIN rw0_wd_in[178]
    DIRECTION INPUT ;
    USE SIGNAL ;
    SHAPE ABUTMENT ;
    PORT
      LAYER met2 ;
      RECT 240.050 0.000 240.190 0.420 ;
    END
  END rw0_wd_in[178]
  PIN rw0_wd_in[179]
    DIRECTION INPUT ;
    USE SIGNAL ;
    SHAPE ABUTMENT ;
    PORT
      LAYER met2 ;
      RECT 242.810 0.000 242.950 0.420 ;
    END
  END rw0_wd_in[179]
  PIN rw0_wd_in[180]
    DIRECTION INPUT ;
    USE SIGNAL ;
    SHAPE ABUTMENT ;
    PORT
      LAYER met2 ;
      RECT 245.570 0.000 245.710 0.420 ;
    END
  END rw0_wd_in[180]
  PIN rw0_wd_in[181]
    DIRECTION INPUT ;
    USE SIGNAL ;
    SHAPE ABUTMENT ;
    PORT
      LAYER met2 ;
      RECT 248.330 0.000 248.470 0.420 ;
    END
  END rw0_wd_in[181]
  PIN rw0_wd_in[182]
    DIRECTION INPUT ;
    USE SIGNAL ;
    SHAPE ABUTMENT ;
    PORT
      LAYER met2 ;
      RECT 251.090 0.000 251.230 0.420 ;
    END
  END rw0_wd_in[182]
  PIN rw0_wd_in[183]
    DIRECTION INPUT ;
    USE SIGNAL ;
    SHAPE ABUTMENT ;
    PORT
      LAYER met2 ;
      RECT 253.850 0.000 253.990 0.420 ;
    END
  END rw0_wd_in[183]
  PIN rw0_rd_out[0]
    DIRECTION OUTPUT ;
    USE SIGNAL ;
    SHAPE ABUTMENT ;
    PORT
      LAYER met2 ;
      RECT 256.610 0.000 256.750 0.420 ;
    END
  END rw0_rd_out[0]
  PIN rw0_rd_out[1]
    DIRECTION OUTPUT ;
    USE SIGNAL ;
    SHAPE ABUTMENT ;
    PORT
      LAYER met2 ;
      RECT 259.370 0.000 259.510 0.420 ;
    END
  END rw0_rd_out[1]
  PIN rw0_rd_out[2]
    DIRECTION OUTPUT ;
    USE SIGNAL ;
    SHAPE ABUTMENT ;
    PORT
      LAYER met2 ;
      RECT 262.130 0.000 262.270 0.420 ;
    END
  END rw0_rd_out[2]
  PIN rw0_rd_out[3]
    DIRECTION OUTPUT ;
    USE SIGNAL ;
    SHAPE ABUTMENT ;
    PORT
      LAYER met2 ;
      RECT 264.890 0.000 265.030 0.420 ;
    END
  END rw0_rd_out[3]
  PIN rw0_rd_out[4]
    DIRECTION OUTPUT ;
    USE SIGNAL ;
    SHAPE ABUTMENT ;
    PORT
      LAYER met2 ;
      RECT 267.650 0.000 267.790 0.420 ;
    END
  END rw0_rd_out[4]
  PIN rw0_rd_out[5]
    DIRECTION OUTPUT ;
    USE SIGNAL ;
    SHAPE ABUTMENT ;
    PORT
      LAYER met2 ;
      RECT 270.410 0.000 270.550 0.420 ;
    END
  END rw0_rd_out[5]
  PIN rw0_rd_out[6]
    DIRECTION OUTPUT ;
    USE SIGNAL ;
    SHAPE ABUTMENT ;
    PORT
      LAYER met2 ;
      RECT 273.170 0.000 273.310 0.420 ;
    END
  END rw0_rd_out[6]
  PIN rw0_rd_out[7]
    DIRECTION OUTPUT ;
    USE SIGNAL ;
    SHAPE ABUTMENT ;
    PORT
      LAYER met2 ;
      RECT 275.930 0.000 276.070 0.420 ;
    END
  END rw0_rd_out[7]
  PIN rw0_rd_out[8]
    DIRECTION OUTPUT ;
    USE SIGNAL ;
    SHAPE ABUTMENT ;
    PORT
      LAYER met2 ;
      RECT 278.690 0.000 278.830 0.420 ;
    END
  END rw0_rd_out[8]
  PIN rw0_rd_out[9]
    DIRECTION OUTPUT ;
    USE SIGNAL ;
    SHAPE ABUTMENT ;
    PORT
      LAYER met2 ;
      RECT 281.450 0.000 281.590 0.420 ;
    END
  END rw0_rd_out[9]
  PIN rw0_rd_out[10]
    DIRECTION OUTPUT ;
    USE SIGNAL ;
    SHAPE ABUTMENT ;
    PORT
      LAYER met2 ;
      RECT 284.210 0.000 284.350 0.420 ;
    END
  END rw0_rd_out[10]
  PIN rw0_rd_out[11]
    DIRECTION OUTPUT ;
    USE SIGNAL ;
    SHAPE ABUTMENT ;
    PORT
      LAYER met2 ;
      RECT 286.970 0.000 287.110 0.420 ;
    END
  END rw0_rd_out[11]
  PIN rw0_rd_out[12]
    DIRECTION OUTPUT ;
    USE SIGNAL ;
    SHAPE ABUTMENT ;
    PORT
      LAYER met2 ;
      RECT 289.730 0.000 289.870 0.420 ;
    END
  END rw0_rd_out[12]
  PIN rw0_rd_out[13]
    DIRECTION OUTPUT ;
    USE SIGNAL ;
    SHAPE ABUTMENT ;
    PORT
      LAYER met2 ;
      RECT 292.490 0.000 292.630 0.420 ;
    END
  END rw0_rd_out[13]
  PIN rw0_rd_out[14]
    DIRECTION OUTPUT ;
    USE SIGNAL ;
    SHAPE ABUTMENT ;
    PORT
      LAYER met2 ;
      RECT 295.250 0.000 295.390 0.420 ;
    END
  END rw0_rd_out[14]
  PIN rw0_rd_out[15]
    DIRECTION OUTPUT ;
    USE SIGNAL ;
    SHAPE ABUTMENT ;
    PORT
      LAYER met2 ;
      RECT 298.010 0.000 298.150 0.420 ;
    END
  END rw0_rd_out[15]
  PIN rw0_rd_out[16]
    DIRECTION OUTPUT ;
    USE SIGNAL ;
    SHAPE ABUTMENT ;
    PORT
      LAYER met2 ;
      RECT 300.770 0.000 300.910 0.420 ;
    END
  END rw0_rd_out[16]
  PIN rw0_rd_out[17]
    DIRECTION OUTPUT ;
    USE SIGNAL ;
    SHAPE ABUTMENT ;
    PORT
      LAYER met2 ;
      RECT 303.530 0.000 303.670 0.420 ;
    END
  END rw0_rd_out[17]
  PIN rw0_rd_out[18]
    DIRECTION OUTPUT ;
    USE SIGNAL ;
    SHAPE ABUTMENT ;
    PORT
      LAYER met2 ;
      RECT 306.290 0.000 306.430 0.420 ;
    END
  END rw0_rd_out[18]
  PIN rw0_rd_out[19]
    DIRECTION OUTPUT ;
    USE SIGNAL ;
    SHAPE ABUTMENT ;
    PORT
      LAYER met2 ;
      RECT 309.050 0.000 309.190 0.420 ;
    END
  END rw0_rd_out[19]
  PIN rw0_rd_out[20]
    DIRECTION OUTPUT ;
    USE SIGNAL ;
    SHAPE ABUTMENT ;
    PORT
      LAYER met2 ;
      RECT 311.810 0.000 311.950 0.420 ;
    END
  END rw0_rd_out[20]
  PIN rw0_rd_out[21]
    DIRECTION OUTPUT ;
    USE SIGNAL ;
    SHAPE ABUTMENT ;
    PORT
      LAYER met2 ;
      RECT 314.570 0.000 314.710 0.420 ;
    END
  END rw0_rd_out[21]
  PIN rw0_rd_out[22]
    DIRECTION OUTPUT ;
    USE SIGNAL ;
    SHAPE ABUTMENT ;
    PORT
      LAYER met2 ;
      RECT 317.330 0.000 317.470 0.420 ;
    END
  END rw0_rd_out[22]
  PIN rw0_rd_out[23]
    DIRECTION OUTPUT ;
    USE SIGNAL ;
    SHAPE ABUTMENT ;
    PORT
      LAYER met2 ;
      RECT 320.090 0.000 320.230 0.420 ;
    END
  END rw0_rd_out[23]
  PIN rw0_rd_out[24]
    DIRECTION OUTPUT ;
    USE SIGNAL ;
    SHAPE ABUTMENT ;
    PORT
      LAYER met2 ;
      RECT 322.850 0.000 322.990 0.420 ;
    END
  END rw0_rd_out[24]
  PIN rw0_rd_out[25]
    DIRECTION OUTPUT ;
    USE SIGNAL ;
    SHAPE ABUTMENT ;
    PORT
      LAYER met2 ;
      RECT 325.610 0.000 325.750 0.420 ;
    END
  END rw0_rd_out[25]
  PIN rw0_rd_out[26]
    DIRECTION OUTPUT ;
    USE SIGNAL ;
    SHAPE ABUTMENT ;
    PORT
      LAYER met2 ;
      RECT 328.370 0.000 328.510 0.420 ;
    END
  END rw0_rd_out[26]
  PIN rw0_rd_out[27]
    DIRECTION OUTPUT ;
    USE SIGNAL ;
    SHAPE ABUTMENT ;
    PORT
      LAYER met2 ;
      RECT 331.130 0.000 331.270 0.420 ;
    END
  END rw0_rd_out[27]
  PIN rw0_rd_out[28]
    DIRECTION OUTPUT ;
    USE SIGNAL ;
    SHAPE ABUTMENT ;
    PORT
      LAYER met2 ;
      RECT 333.890 0.000 334.030 0.420 ;
    END
  END rw0_rd_out[28]
  PIN rw0_rd_out[29]
    DIRECTION OUTPUT ;
    USE SIGNAL ;
    SHAPE ABUTMENT ;
    PORT
      LAYER met2 ;
      RECT 336.650 0.000 336.790 0.420 ;
    END
  END rw0_rd_out[29]
  PIN rw0_rd_out[30]
    DIRECTION OUTPUT ;
    USE SIGNAL ;
    SHAPE ABUTMENT ;
    PORT
      LAYER met2 ;
      RECT 339.410 0.000 339.550 0.420 ;
    END
  END rw0_rd_out[30]
  PIN rw0_rd_out[31]
    DIRECTION OUTPUT ;
    USE SIGNAL ;
    SHAPE ABUTMENT ;
    PORT
      LAYER met2 ;
      RECT 342.170 0.000 342.310 0.420 ;
    END
  END rw0_rd_out[31]
  PIN rw0_rd_out[32]
    DIRECTION OUTPUT ;
    USE SIGNAL ;
    SHAPE ABUTMENT ;
    PORT
      LAYER met2 ;
      RECT 344.930 0.000 345.070 0.420 ;
    END
  END rw0_rd_out[32]
  PIN rw0_rd_out[33]
    DIRECTION OUTPUT ;
    USE SIGNAL ;
    SHAPE ABUTMENT ;
    PORT
      LAYER met2 ;
      RECT 347.690 0.000 347.830 0.420 ;
    END
  END rw0_rd_out[33]
  PIN rw0_rd_out[34]
    DIRECTION OUTPUT ;
    USE SIGNAL ;
    SHAPE ABUTMENT ;
    PORT
      LAYER met2 ;
      RECT 350.450 0.000 350.590 0.420 ;
    END
  END rw0_rd_out[34]
  PIN rw0_rd_out[35]
    DIRECTION OUTPUT ;
    USE SIGNAL ;
    SHAPE ABUTMENT ;
    PORT
      LAYER met2 ;
      RECT 353.210 0.000 353.350 0.420 ;
    END
  END rw0_rd_out[35]
  PIN rw0_rd_out[36]
    DIRECTION OUTPUT ;
    USE SIGNAL ;
    SHAPE ABUTMENT ;
    PORT
      LAYER met2 ;
      RECT 355.970 0.000 356.110 0.420 ;
    END
  END rw0_rd_out[36]
  PIN rw0_rd_out[37]
    DIRECTION OUTPUT ;
    USE SIGNAL ;
    SHAPE ABUTMENT ;
    PORT
      LAYER met2 ;
      RECT 358.730 0.000 358.870 0.420 ;
    END
  END rw0_rd_out[37]
  PIN rw0_rd_out[38]
    DIRECTION OUTPUT ;
    USE SIGNAL ;
    SHAPE ABUTMENT ;
    PORT
      LAYER met2 ;
      RECT 361.490 0.000 361.630 0.420 ;
    END
  END rw0_rd_out[38]
  PIN rw0_rd_out[39]
    DIRECTION OUTPUT ;
    USE SIGNAL ;
    SHAPE ABUTMENT ;
    PORT
      LAYER met2 ;
      RECT 364.250 0.000 364.390 0.420 ;
    END
  END rw0_rd_out[39]
  PIN rw0_rd_out[40]
    DIRECTION OUTPUT ;
    USE SIGNAL ;
    SHAPE ABUTMENT ;
    PORT
      LAYER met2 ;
      RECT 367.010 0.000 367.150 0.420 ;
    END
  END rw0_rd_out[40]
  PIN rw0_rd_out[41]
    DIRECTION OUTPUT ;
    USE SIGNAL ;
    SHAPE ABUTMENT ;
    PORT
      LAYER met2 ;
      RECT 369.770 0.000 369.910 0.420 ;
    END
  END rw0_rd_out[41]
  PIN rw0_rd_out[42]
    DIRECTION OUTPUT ;
    USE SIGNAL ;
    SHAPE ABUTMENT ;
    PORT
      LAYER met2 ;
      RECT 372.530 0.000 372.670 0.420 ;
    END
  END rw0_rd_out[42]
  PIN rw0_rd_out[43]
    DIRECTION OUTPUT ;
    USE SIGNAL ;
    SHAPE ABUTMENT ;
    PORT
      LAYER met2 ;
      RECT 375.290 0.000 375.430 0.420 ;
    END
  END rw0_rd_out[43]
  PIN rw0_rd_out[44]
    DIRECTION OUTPUT ;
    USE SIGNAL ;
    SHAPE ABUTMENT ;
    PORT
      LAYER met2 ;
      RECT 378.050 0.000 378.190 0.420 ;
    END
  END rw0_rd_out[44]
  PIN rw0_rd_out[45]
    DIRECTION OUTPUT ;
    USE SIGNAL ;
    SHAPE ABUTMENT ;
    PORT
      LAYER met2 ;
      RECT 380.810 0.000 380.950 0.420 ;
    END
  END rw0_rd_out[45]
  PIN rw0_rd_out[46]
    DIRECTION OUTPUT ;
    USE SIGNAL ;
    SHAPE ABUTMENT ;
    PORT
      LAYER met2 ;
      RECT 383.570 0.000 383.710 0.420 ;
    END
  END rw0_rd_out[46]
  PIN rw0_rd_out[47]
    DIRECTION OUTPUT ;
    USE SIGNAL ;
    SHAPE ABUTMENT ;
    PORT
      LAYER met2 ;
      RECT 386.330 0.000 386.470 0.420 ;
    END
  END rw0_rd_out[47]
  PIN rw0_rd_out[48]
    DIRECTION OUTPUT ;
    USE SIGNAL ;
    SHAPE ABUTMENT ;
    PORT
      LAYER met2 ;
      RECT 389.090 0.000 389.230 0.420 ;
    END
  END rw0_rd_out[48]
  PIN rw0_rd_out[49]
    DIRECTION OUTPUT ;
    USE SIGNAL ;
    SHAPE ABUTMENT ;
    PORT
      LAYER met2 ;
      RECT 391.850 0.000 391.990 0.420 ;
    END
  END rw0_rd_out[49]
  PIN rw0_rd_out[50]
    DIRECTION OUTPUT ;
    USE SIGNAL ;
    SHAPE ABUTMENT ;
    PORT
      LAYER met2 ;
      RECT 394.610 0.000 394.750 0.420 ;
    END
  END rw0_rd_out[50]
  PIN rw0_rd_out[51]
    DIRECTION OUTPUT ;
    USE SIGNAL ;
    SHAPE ABUTMENT ;
    PORT
      LAYER met2 ;
      RECT 397.370 0.000 397.510 0.420 ;
    END
  END rw0_rd_out[51]
  PIN rw0_rd_out[52]
    DIRECTION OUTPUT ;
    USE SIGNAL ;
    SHAPE ABUTMENT ;
    PORT
      LAYER met2 ;
      RECT 400.130 0.000 400.270 0.420 ;
    END
  END rw0_rd_out[52]
  PIN rw0_rd_out[53]
    DIRECTION OUTPUT ;
    USE SIGNAL ;
    SHAPE ABUTMENT ;
    PORT
      LAYER met2 ;
      RECT 402.890 0.000 403.030 0.420 ;
    END
  END rw0_rd_out[53]
  PIN rw0_rd_out[54]
    DIRECTION OUTPUT ;
    USE SIGNAL ;
    SHAPE ABUTMENT ;
    PORT
      LAYER met2 ;
      RECT 405.650 0.000 405.790 0.420 ;
    END
  END rw0_rd_out[54]
  PIN rw0_rd_out[55]
    DIRECTION OUTPUT ;
    USE SIGNAL ;
    SHAPE ABUTMENT ;
    PORT
      LAYER met2 ;
      RECT 408.410 0.000 408.550 0.420 ;
    END
  END rw0_rd_out[55]
  PIN rw0_rd_out[56]
    DIRECTION OUTPUT ;
    USE SIGNAL ;
    SHAPE ABUTMENT ;
    PORT
      LAYER met2 ;
      RECT 411.170 0.000 411.310 0.420 ;
    END
  END rw0_rd_out[56]
  PIN rw0_rd_out[57]
    DIRECTION OUTPUT ;
    USE SIGNAL ;
    SHAPE ABUTMENT ;
    PORT
      LAYER met2 ;
      RECT 413.930 0.000 414.070 0.420 ;
    END
  END rw0_rd_out[57]
  PIN rw0_rd_out[58]
    DIRECTION OUTPUT ;
    USE SIGNAL ;
    SHAPE ABUTMENT ;
    PORT
      LAYER met2 ;
      RECT 416.690 0.000 416.830 0.420 ;
    END
  END rw0_rd_out[58]
  PIN rw0_rd_out[59]
    DIRECTION OUTPUT ;
    USE SIGNAL ;
    SHAPE ABUTMENT ;
    PORT
      LAYER met2 ;
      RECT 419.450 0.000 419.590 0.420 ;
    END
  END rw0_rd_out[59]
  PIN rw0_rd_out[60]
    DIRECTION OUTPUT ;
    USE SIGNAL ;
    SHAPE ABUTMENT ;
    PORT
      LAYER met2 ;
      RECT 422.210 0.000 422.350 0.420 ;
    END
  END rw0_rd_out[60]
  PIN rw0_rd_out[61]
    DIRECTION OUTPUT ;
    USE SIGNAL ;
    SHAPE ABUTMENT ;
    PORT
      LAYER met2 ;
      RECT 424.970 0.000 425.110 0.420 ;
    END
  END rw0_rd_out[61]
  PIN rw0_rd_out[62]
    DIRECTION OUTPUT ;
    USE SIGNAL ;
    SHAPE ABUTMENT ;
    PORT
      LAYER met2 ;
      RECT 427.730 0.000 427.870 0.420 ;
    END
  END rw0_rd_out[62]
  PIN rw0_rd_out[63]
    DIRECTION OUTPUT ;
    USE SIGNAL ;
    SHAPE ABUTMENT ;
    PORT
      LAYER met2 ;
      RECT 430.490 0.000 430.630 0.420 ;
    END
  END rw0_rd_out[63]
  PIN rw0_rd_out[64]
    DIRECTION OUTPUT ;
    USE SIGNAL ;
    SHAPE ABUTMENT ;
    PORT
      LAYER met2 ;
      RECT 433.250 0.000 433.390 0.420 ;
    END
  END rw0_rd_out[64]
  PIN rw0_rd_out[65]
    DIRECTION OUTPUT ;
    USE SIGNAL ;
    SHAPE ABUTMENT ;
    PORT
      LAYER met2 ;
      RECT 436.010 0.000 436.150 0.420 ;
    END
  END rw0_rd_out[65]
  PIN rw0_rd_out[66]
    DIRECTION OUTPUT ;
    USE SIGNAL ;
    SHAPE ABUTMENT ;
    PORT
      LAYER met2 ;
      RECT 438.770 0.000 438.910 0.420 ;
    END
  END rw0_rd_out[66]
  PIN rw0_rd_out[67]
    DIRECTION OUTPUT ;
    USE SIGNAL ;
    SHAPE ABUTMENT ;
    PORT
      LAYER met2 ;
      RECT 441.530 0.000 441.670 0.420 ;
    END
  END rw0_rd_out[67]
  PIN rw0_rd_out[68]
    DIRECTION OUTPUT ;
    USE SIGNAL ;
    SHAPE ABUTMENT ;
    PORT
      LAYER met2 ;
      RECT 444.290 0.000 444.430 0.420 ;
    END
  END rw0_rd_out[68]
  PIN rw0_rd_out[69]
    DIRECTION OUTPUT ;
    USE SIGNAL ;
    SHAPE ABUTMENT ;
    PORT
      LAYER met2 ;
      RECT 447.050 0.000 447.190 0.420 ;
    END
  END rw0_rd_out[69]
  PIN rw0_rd_out[70]
    DIRECTION OUTPUT ;
    USE SIGNAL ;
    SHAPE ABUTMENT ;
    PORT
      LAYER met2 ;
      RECT 449.810 0.000 449.950 0.420 ;
    END
  END rw0_rd_out[70]
  PIN rw0_rd_out[71]
    DIRECTION OUTPUT ;
    USE SIGNAL ;
    SHAPE ABUTMENT ;
    PORT
      LAYER met2 ;
      RECT 452.570 0.000 452.710 0.420 ;
    END
  END rw0_rd_out[71]
  PIN rw0_rd_out[72]
    DIRECTION OUTPUT ;
    USE SIGNAL ;
    SHAPE ABUTMENT ;
    PORT
      LAYER met2 ;
      RECT 455.330 0.000 455.470 0.420 ;
    END
  END rw0_rd_out[72]
  PIN rw0_rd_out[73]
    DIRECTION OUTPUT ;
    USE SIGNAL ;
    SHAPE ABUTMENT ;
    PORT
      LAYER met2 ;
      RECT 458.090 0.000 458.230 0.420 ;
    END
  END rw0_rd_out[73]
  PIN rw0_rd_out[74]
    DIRECTION OUTPUT ;
    USE SIGNAL ;
    SHAPE ABUTMENT ;
    PORT
      LAYER met2 ;
      RECT 460.850 0.000 460.990 0.420 ;
    END
  END rw0_rd_out[74]
  PIN rw0_rd_out[75]
    DIRECTION OUTPUT ;
    USE SIGNAL ;
    SHAPE ABUTMENT ;
    PORT
      LAYER met2 ;
      RECT 463.610 0.000 463.750 0.420 ;
    END
  END rw0_rd_out[75]
  PIN rw0_rd_out[76]
    DIRECTION OUTPUT ;
    USE SIGNAL ;
    SHAPE ABUTMENT ;
    PORT
      LAYER met2 ;
      RECT 466.370 0.000 466.510 0.420 ;
    END
  END rw0_rd_out[76]
  PIN rw0_rd_out[77]
    DIRECTION OUTPUT ;
    USE SIGNAL ;
    SHAPE ABUTMENT ;
    PORT
      LAYER met2 ;
      RECT 469.130 0.000 469.270 0.420 ;
    END
  END rw0_rd_out[77]
  PIN rw0_rd_out[78]
    DIRECTION OUTPUT ;
    USE SIGNAL ;
    SHAPE ABUTMENT ;
    PORT
      LAYER met2 ;
      RECT 471.890 0.000 472.030 0.420 ;
    END
  END rw0_rd_out[78]
  PIN rw0_rd_out[79]
    DIRECTION OUTPUT ;
    USE SIGNAL ;
    SHAPE ABUTMENT ;
    PORT
      LAYER met2 ;
      RECT 474.650 0.000 474.790 0.420 ;
    END
  END rw0_rd_out[79]
  PIN rw0_rd_out[80]
    DIRECTION OUTPUT ;
    USE SIGNAL ;
    SHAPE ABUTMENT ;
    PORT
      LAYER met2 ;
      RECT 477.410 0.000 477.550 0.420 ;
    END
  END rw0_rd_out[80]
  PIN rw0_rd_out[81]
    DIRECTION OUTPUT ;
    USE SIGNAL ;
    SHAPE ABUTMENT ;
    PORT
      LAYER met2 ;
      RECT 480.170 0.000 480.310 0.420 ;
    END
  END rw0_rd_out[81]
  PIN rw0_rd_out[82]
    DIRECTION OUTPUT ;
    USE SIGNAL ;
    SHAPE ABUTMENT ;
    PORT
      LAYER met2 ;
      RECT 482.930 0.000 483.070 0.420 ;
    END
  END rw0_rd_out[82]
  PIN rw0_rd_out[83]
    DIRECTION OUTPUT ;
    USE SIGNAL ;
    SHAPE ABUTMENT ;
    PORT
      LAYER met2 ;
      RECT 485.690 0.000 485.830 0.420 ;
    END
  END rw0_rd_out[83]
  PIN rw0_rd_out[84]
    DIRECTION OUTPUT ;
    USE SIGNAL ;
    SHAPE ABUTMENT ;
    PORT
      LAYER met2 ;
      RECT 488.450 0.000 488.590 0.420 ;
    END
  END rw0_rd_out[84]
  PIN rw0_rd_out[85]
    DIRECTION OUTPUT ;
    USE SIGNAL ;
    SHAPE ABUTMENT ;
    PORT
      LAYER met2 ;
      RECT 491.210 0.000 491.350 0.420 ;
    END
  END rw0_rd_out[85]
  PIN rw0_rd_out[86]
    DIRECTION OUTPUT ;
    USE SIGNAL ;
    SHAPE ABUTMENT ;
    PORT
      LAYER met2 ;
      RECT 493.970 0.000 494.110 0.420 ;
    END
  END rw0_rd_out[86]
  PIN rw0_rd_out[87]
    DIRECTION OUTPUT ;
    USE SIGNAL ;
    SHAPE ABUTMENT ;
    PORT
      LAYER met2 ;
      RECT 496.730 0.000 496.870 0.420 ;
    END
  END rw0_rd_out[87]
  PIN rw0_rd_out[88]
    DIRECTION OUTPUT ;
    USE SIGNAL ;
    SHAPE ABUTMENT ;
    PORT
      LAYER met2 ;
      RECT 499.490 0.000 499.630 0.420 ;
    END
  END rw0_rd_out[88]
  PIN rw0_rd_out[89]
    DIRECTION OUTPUT ;
    USE SIGNAL ;
    SHAPE ABUTMENT ;
    PORT
      LAYER met2 ;
      RECT 502.250 0.000 502.390 0.420 ;
    END
  END rw0_rd_out[89]
  PIN rw0_rd_out[90]
    DIRECTION OUTPUT ;
    USE SIGNAL ;
    SHAPE ABUTMENT ;
    PORT
      LAYER met2 ;
      RECT 505.010 0.000 505.150 0.420 ;
    END
  END rw0_rd_out[90]
  PIN rw0_rd_out[91]
    DIRECTION OUTPUT ;
    USE SIGNAL ;
    SHAPE ABUTMENT ;
    PORT
      LAYER met2 ;
      RECT 507.770 0.000 507.910 0.420 ;
    END
  END rw0_rd_out[91]
  PIN rw0_rd_out[92]
    DIRECTION OUTPUT ;
    USE SIGNAL ;
    SHAPE ABUTMENT ;
    PORT
      LAYER met2 ;
      RECT 214.290 290.620 214.430 291.040 ;
    END
  END rw0_rd_out[92]
  PIN rw0_rd_out[93]
    DIRECTION OUTPUT ;
    USE SIGNAL ;
    SHAPE ABUTMENT ;
    PORT
      LAYER met2 ;
      RECT 216.590 290.620 216.730 291.040 ;
    END
  END rw0_rd_out[93]
  PIN rw0_rd_out[94]
    DIRECTION OUTPUT ;
    USE SIGNAL ;
    SHAPE ABUTMENT ;
    PORT
      LAYER met2 ;
      RECT 218.890 290.620 219.030 291.040 ;
    END
  END rw0_rd_out[94]
  PIN rw0_rd_out[95]
    DIRECTION OUTPUT ;
    USE SIGNAL ;
    SHAPE ABUTMENT ;
    PORT
      LAYER met2 ;
      RECT 221.190 290.620 221.330 291.040 ;
    END
  END rw0_rd_out[95]
  PIN rw0_rd_out[96]
    DIRECTION OUTPUT ;
    USE SIGNAL ;
    SHAPE ABUTMENT ;
    PORT
      LAYER met2 ;
      RECT 223.490 290.620 223.630 291.040 ;
    END
  END rw0_rd_out[96]
  PIN rw0_rd_out[97]
    DIRECTION OUTPUT ;
    USE SIGNAL ;
    SHAPE ABUTMENT ;
    PORT
      LAYER met2 ;
      RECT 225.790 290.620 225.930 291.040 ;
    END
  END rw0_rd_out[97]
  PIN rw0_rd_out[98]
    DIRECTION OUTPUT ;
    USE SIGNAL ;
    SHAPE ABUTMENT ;
    PORT
      LAYER met2 ;
      RECT 228.090 290.620 228.230 291.040 ;
    END
  END rw0_rd_out[98]
  PIN rw0_rd_out[99]
    DIRECTION OUTPUT ;
    USE SIGNAL ;
    SHAPE ABUTMENT ;
    PORT
      LAYER met2 ;
      RECT 230.390 290.620 230.530 291.040 ;
    END
  END rw0_rd_out[99]
  PIN rw0_rd_out[100]
    DIRECTION OUTPUT ;
    USE SIGNAL ;
    SHAPE ABUTMENT ;
    PORT
      LAYER met2 ;
      RECT 232.690 290.620 232.830 291.040 ;
    END
  END rw0_rd_out[100]
  PIN rw0_rd_out[101]
    DIRECTION OUTPUT ;
    USE SIGNAL ;
    SHAPE ABUTMENT ;
    PORT
      LAYER met2 ;
      RECT 234.990 290.620 235.130 291.040 ;
    END
  END rw0_rd_out[101]
  PIN rw0_rd_out[102]
    DIRECTION OUTPUT ;
    USE SIGNAL ;
    SHAPE ABUTMENT ;
    PORT
      LAYER met2 ;
      RECT 237.290 290.620 237.430 291.040 ;
    END
  END rw0_rd_out[102]
  PIN rw0_rd_out[103]
    DIRECTION OUTPUT ;
    USE SIGNAL ;
    SHAPE ABUTMENT ;
    PORT
      LAYER met2 ;
      RECT 239.590 290.620 239.730 291.040 ;
    END
  END rw0_rd_out[103]
  PIN rw0_rd_out[104]
    DIRECTION OUTPUT ;
    USE SIGNAL ;
    SHAPE ABUTMENT ;
    PORT
      LAYER met2 ;
      RECT 241.890 290.620 242.030 291.040 ;
    END
  END rw0_rd_out[104]
  PIN rw0_rd_out[105]
    DIRECTION OUTPUT ;
    USE SIGNAL ;
    SHAPE ABUTMENT ;
    PORT
      LAYER met2 ;
      RECT 244.190 290.620 244.330 291.040 ;
    END
  END rw0_rd_out[105]
  PIN rw0_rd_out[106]
    DIRECTION OUTPUT ;
    USE SIGNAL ;
    SHAPE ABUTMENT ;
    PORT
      LAYER met2 ;
      RECT 246.490 290.620 246.630 291.040 ;
    END
  END rw0_rd_out[106]
  PIN rw0_rd_out[107]
    DIRECTION OUTPUT ;
    USE SIGNAL ;
    SHAPE ABUTMENT ;
    PORT
      LAYER met2 ;
      RECT 248.790 290.620 248.930 291.040 ;
    END
  END rw0_rd_out[107]
  PIN rw0_rd_out[108]
    DIRECTION OUTPUT ;
    USE SIGNAL ;
    SHAPE ABUTMENT ;
    PORT
      LAYER met2 ;
      RECT 251.090 290.620 251.230 291.040 ;
    END
  END rw0_rd_out[108]
  PIN rw0_rd_out[109]
    DIRECTION OUTPUT ;
    USE SIGNAL ;
    SHAPE ABUTMENT ;
    PORT
      LAYER met2 ;
      RECT 253.390 290.620 253.530 291.040 ;
    END
  END rw0_rd_out[109]
  PIN rw0_rd_out[110]
    DIRECTION OUTPUT ;
    USE SIGNAL ;
    SHAPE ABUTMENT ;
    PORT
      LAYER met2 ;
      RECT 255.690 290.620 255.830 291.040 ;
    END
  END rw0_rd_out[110]
  PIN rw0_rd_out[111]
    DIRECTION OUTPUT ;
    USE SIGNAL ;
    SHAPE ABUTMENT ;
    PORT
      LAYER met2 ;
      RECT 257.990 290.620 258.130 291.040 ;
    END
  END rw0_rd_out[111]
  PIN rw0_rd_out[112]
    DIRECTION OUTPUT ;
    USE SIGNAL ;
    SHAPE ABUTMENT ;
    PORT
      LAYER met2 ;
      RECT 260.290 290.620 260.430 291.040 ;
    END
  END rw0_rd_out[112]
  PIN rw0_rd_out[113]
    DIRECTION OUTPUT ;
    USE SIGNAL ;
    SHAPE ABUTMENT ;
    PORT
      LAYER met2 ;
      RECT 262.590 290.620 262.730 291.040 ;
    END
  END rw0_rd_out[113]
  PIN rw0_rd_out[114]
    DIRECTION OUTPUT ;
    USE SIGNAL ;
    SHAPE ABUTMENT ;
    PORT
      LAYER met2 ;
      RECT 264.890 290.620 265.030 291.040 ;
    END
  END rw0_rd_out[114]
  PIN rw0_rd_out[115]
    DIRECTION OUTPUT ;
    USE SIGNAL ;
    SHAPE ABUTMENT ;
    PORT
      LAYER met2 ;
      RECT 267.190 290.620 267.330 291.040 ;
    END
  END rw0_rd_out[115]
  PIN rw0_rd_out[116]
    DIRECTION OUTPUT ;
    USE SIGNAL ;
    SHAPE ABUTMENT ;
    PORT
      LAYER met2 ;
      RECT 269.490 290.620 269.630 291.040 ;
    END
  END rw0_rd_out[116]
  PIN rw0_rd_out[117]
    DIRECTION OUTPUT ;
    USE SIGNAL ;
    SHAPE ABUTMENT ;
    PORT
      LAYER met2 ;
      RECT 271.790 290.620 271.930 291.040 ;
    END
  END rw0_rd_out[117]
  PIN rw0_rd_out[118]
    DIRECTION OUTPUT ;
    USE SIGNAL ;
    SHAPE ABUTMENT ;
    PORT
      LAYER met2 ;
      RECT 274.090 290.620 274.230 291.040 ;
    END
  END rw0_rd_out[118]
  PIN rw0_rd_out[119]
    DIRECTION OUTPUT ;
    USE SIGNAL ;
    SHAPE ABUTMENT ;
    PORT
      LAYER met2 ;
      RECT 276.390 290.620 276.530 291.040 ;
    END
  END rw0_rd_out[119]
  PIN rw0_rd_out[120]
    DIRECTION OUTPUT ;
    USE SIGNAL ;
    SHAPE ABUTMENT ;
    PORT
      LAYER met2 ;
      RECT 278.690 290.620 278.830 291.040 ;
    END
  END rw0_rd_out[120]
  PIN rw0_rd_out[121]
    DIRECTION OUTPUT ;
    USE SIGNAL ;
    SHAPE ABUTMENT ;
    PORT
      LAYER met2 ;
      RECT 280.990 290.620 281.130 291.040 ;
    END
  END rw0_rd_out[121]
  PIN rw0_rd_out[122]
    DIRECTION OUTPUT ;
    USE SIGNAL ;
    SHAPE ABUTMENT ;
    PORT
      LAYER met2 ;
      RECT 283.290 290.620 283.430 291.040 ;
    END
  END rw0_rd_out[122]
  PIN rw0_rd_out[123]
    DIRECTION OUTPUT ;
    USE SIGNAL ;
    SHAPE ABUTMENT ;
    PORT
      LAYER met2 ;
      RECT 285.590 290.620 285.730 291.040 ;
    END
  END rw0_rd_out[123]
  PIN rw0_rd_out[124]
    DIRECTION OUTPUT ;
    USE SIGNAL ;
    SHAPE ABUTMENT ;
    PORT
      LAYER met2 ;
      RECT 287.890 290.620 288.030 291.040 ;
    END
  END rw0_rd_out[124]
  PIN rw0_rd_out[125]
    DIRECTION OUTPUT ;
    USE SIGNAL ;
    SHAPE ABUTMENT ;
    PORT
      LAYER met2 ;
      RECT 290.190 290.620 290.330 291.040 ;
    END
  END rw0_rd_out[125]
  PIN rw0_rd_out[126]
    DIRECTION OUTPUT ;
    USE SIGNAL ;
    SHAPE ABUTMENT ;
    PORT
      LAYER met2 ;
      RECT 292.490 290.620 292.630 291.040 ;
    END
  END rw0_rd_out[126]
  PIN rw0_rd_out[127]
    DIRECTION OUTPUT ;
    USE SIGNAL ;
    SHAPE ABUTMENT ;
    PORT
      LAYER met2 ;
      RECT 294.790 290.620 294.930 291.040 ;
    END
  END rw0_rd_out[127]
  PIN rw0_rd_out[128]
    DIRECTION OUTPUT ;
    USE SIGNAL ;
    SHAPE ABUTMENT ;
    PORT
      LAYER met2 ;
      RECT 297.090 290.620 297.230 291.040 ;
    END
  END rw0_rd_out[128]
  PIN rw0_rd_out[129]
    DIRECTION OUTPUT ;
    USE SIGNAL ;
    SHAPE ABUTMENT ;
    PORT
      LAYER met2 ;
      RECT 299.390 290.620 299.530 291.040 ;
    END
  END rw0_rd_out[129]
  PIN rw0_rd_out[130]
    DIRECTION OUTPUT ;
    USE SIGNAL ;
    SHAPE ABUTMENT ;
    PORT
      LAYER met2 ;
      RECT 301.690 290.620 301.830 291.040 ;
    END
  END rw0_rd_out[130]
  PIN rw0_rd_out[131]
    DIRECTION OUTPUT ;
    USE SIGNAL ;
    SHAPE ABUTMENT ;
    PORT
      LAYER met2 ;
      RECT 303.990 290.620 304.130 291.040 ;
    END
  END rw0_rd_out[131]
  PIN rw0_rd_out[132]
    DIRECTION OUTPUT ;
    USE SIGNAL ;
    SHAPE ABUTMENT ;
    PORT
      LAYER met2 ;
      RECT 306.290 290.620 306.430 291.040 ;
    END
  END rw0_rd_out[132]
  PIN rw0_rd_out[133]
    DIRECTION OUTPUT ;
    USE SIGNAL ;
    SHAPE ABUTMENT ;
    PORT
      LAYER met2 ;
      RECT 308.590 290.620 308.730 291.040 ;
    END
  END rw0_rd_out[133]
  PIN rw0_rd_out[134]
    DIRECTION OUTPUT ;
    USE SIGNAL ;
    SHAPE ABUTMENT ;
    PORT
      LAYER met2 ;
      RECT 310.890 290.620 311.030 291.040 ;
    END
  END rw0_rd_out[134]
  PIN rw0_rd_out[135]
    DIRECTION OUTPUT ;
    USE SIGNAL ;
    SHAPE ABUTMENT ;
    PORT
      LAYER met2 ;
      RECT 313.190 290.620 313.330 291.040 ;
    END
  END rw0_rd_out[135]
  PIN rw0_rd_out[136]
    DIRECTION OUTPUT ;
    USE SIGNAL ;
    SHAPE ABUTMENT ;
    PORT
      LAYER met2 ;
      RECT 315.490 290.620 315.630 291.040 ;
    END
  END rw0_rd_out[136]
  PIN rw0_rd_out[137]
    DIRECTION OUTPUT ;
    USE SIGNAL ;
    SHAPE ABUTMENT ;
    PORT
      LAYER met2 ;
      RECT 317.790 290.620 317.930 291.040 ;
    END
  END rw0_rd_out[137]
  PIN rw0_rd_out[138]
    DIRECTION OUTPUT ;
    USE SIGNAL ;
    SHAPE ABUTMENT ;
    PORT
      LAYER met2 ;
      RECT 320.090 290.620 320.230 291.040 ;
    END
  END rw0_rd_out[138]
  PIN rw0_rd_out[139]
    DIRECTION OUTPUT ;
    USE SIGNAL ;
    SHAPE ABUTMENT ;
    PORT
      LAYER met2 ;
      RECT 322.390 290.620 322.530 291.040 ;
    END
  END rw0_rd_out[139]
  PIN rw0_rd_out[140]
    DIRECTION OUTPUT ;
    USE SIGNAL ;
    SHAPE ABUTMENT ;
    PORT
      LAYER met2 ;
      RECT 324.690 290.620 324.830 291.040 ;
    END
  END rw0_rd_out[140]
  PIN rw0_rd_out[141]
    DIRECTION OUTPUT ;
    USE SIGNAL ;
    SHAPE ABUTMENT ;
    PORT
      LAYER met2 ;
      RECT 326.990 290.620 327.130 291.040 ;
    END
  END rw0_rd_out[141]
  PIN rw0_rd_out[142]
    DIRECTION OUTPUT ;
    USE SIGNAL ;
    SHAPE ABUTMENT ;
    PORT
      LAYER met2 ;
      RECT 329.290 290.620 329.430 291.040 ;
    END
  END rw0_rd_out[142]
  PIN rw0_rd_out[143]
    DIRECTION OUTPUT ;
    USE SIGNAL ;
    SHAPE ABUTMENT ;
    PORT
      LAYER met2 ;
      RECT 331.590 290.620 331.730 291.040 ;
    END
  END rw0_rd_out[143]
  PIN rw0_rd_out[144]
    DIRECTION OUTPUT ;
    USE SIGNAL ;
    SHAPE ABUTMENT ;
    PORT
      LAYER met2 ;
      RECT 333.890 290.620 334.030 291.040 ;
    END
  END rw0_rd_out[144]
  PIN rw0_rd_out[145]
    DIRECTION OUTPUT ;
    USE SIGNAL ;
    SHAPE ABUTMENT ;
    PORT
      LAYER met2 ;
      RECT 336.190 290.620 336.330 291.040 ;
    END
  END rw0_rd_out[145]
  PIN rw0_rd_out[146]
    DIRECTION OUTPUT ;
    USE SIGNAL ;
    SHAPE ABUTMENT ;
    PORT
      LAYER met2 ;
      RECT 338.490 290.620 338.630 291.040 ;
    END
  END rw0_rd_out[146]
  PIN rw0_rd_out[147]
    DIRECTION OUTPUT ;
    USE SIGNAL ;
    SHAPE ABUTMENT ;
    PORT
      LAYER met2 ;
      RECT 340.790 290.620 340.930 291.040 ;
    END
  END rw0_rd_out[147]
  PIN rw0_rd_out[148]
    DIRECTION OUTPUT ;
    USE SIGNAL ;
    SHAPE ABUTMENT ;
    PORT
      LAYER met2 ;
      RECT 343.090 290.620 343.230 291.040 ;
    END
  END rw0_rd_out[148]
  PIN rw0_rd_out[149]
    DIRECTION OUTPUT ;
    USE SIGNAL ;
    SHAPE ABUTMENT ;
    PORT
      LAYER met2 ;
      RECT 345.390 290.620 345.530 291.040 ;
    END
  END rw0_rd_out[149]
  PIN rw0_rd_out[150]
    DIRECTION OUTPUT ;
    USE SIGNAL ;
    SHAPE ABUTMENT ;
    PORT
      LAYER met2 ;
      RECT 347.690 290.620 347.830 291.040 ;
    END
  END rw0_rd_out[150]
  PIN rw0_rd_out[151]
    DIRECTION OUTPUT ;
    USE SIGNAL ;
    SHAPE ABUTMENT ;
    PORT
      LAYER met2 ;
      RECT 349.990 290.620 350.130 291.040 ;
    END
  END rw0_rd_out[151]
  PIN rw0_rd_out[152]
    DIRECTION OUTPUT ;
    USE SIGNAL ;
    SHAPE ABUTMENT ;
    PORT
      LAYER met2 ;
      RECT 352.290 290.620 352.430 291.040 ;
    END
  END rw0_rd_out[152]
  PIN rw0_rd_out[153]
    DIRECTION OUTPUT ;
    USE SIGNAL ;
    SHAPE ABUTMENT ;
    PORT
      LAYER met2 ;
      RECT 354.590 290.620 354.730 291.040 ;
    END
  END rw0_rd_out[153]
  PIN rw0_rd_out[154]
    DIRECTION OUTPUT ;
    USE SIGNAL ;
    SHAPE ABUTMENT ;
    PORT
      LAYER met2 ;
      RECT 356.890 290.620 357.030 291.040 ;
    END
  END rw0_rd_out[154]
  PIN rw0_rd_out[155]
    DIRECTION OUTPUT ;
    USE SIGNAL ;
    SHAPE ABUTMENT ;
    PORT
      LAYER met2 ;
      RECT 359.190 290.620 359.330 291.040 ;
    END
  END rw0_rd_out[155]
  PIN rw0_rd_out[156]
    DIRECTION OUTPUT ;
    USE SIGNAL ;
    SHAPE ABUTMENT ;
    PORT
      LAYER met2 ;
      RECT 361.490 290.620 361.630 291.040 ;
    END
  END rw0_rd_out[156]
  PIN rw0_rd_out[157]
    DIRECTION OUTPUT ;
    USE SIGNAL ;
    SHAPE ABUTMENT ;
    PORT
      LAYER met2 ;
      RECT 363.790 290.620 363.930 291.040 ;
    END
  END rw0_rd_out[157]
  PIN rw0_rd_out[158]
    DIRECTION OUTPUT ;
    USE SIGNAL ;
    SHAPE ABUTMENT ;
    PORT
      LAYER met2 ;
      RECT 366.090 290.620 366.230 291.040 ;
    END
  END rw0_rd_out[158]
  PIN rw0_rd_out[159]
    DIRECTION OUTPUT ;
    USE SIGNAL ;
    SHAPE ABUTMENT ;
    PORT
      LAYER met2 ;
      RECT 368.390 290.620 368.530 291.040 ;
    END
  END rw0_rd_out[159]
  PIN rw0_rd_out[160]
    DIRECTION OUTPUT ;
    USE SIGNAL ;
    SHAPE ABUTMENT ;
    PORT
      LAYER met2 ;
      RECT 370.690 290.620 370.830 291.040 ;
    END
  END rw0_rd_out[160]
  PIN rw0_rd_out[161]
    DIRECTION OUTPUT ;
    USE SIGNAL ;
    SHAPE ABUTMENT ;
    PORT
      LAYER met2 ;
      RECT 372.990 290.620 373.130 291.040 ;
    END
  END rw0_rd_out[161]
  PIN rw0_rd_out[162]
    DIRECTION OUTPUT ;
    USE SIGNAL ;
    SHAPE ABUTMENT ;
    PORT
      LAYER met2 ;
      RECT 375.290 290.620 375.430 291.040 ;
    END
  END rw0_rd_out[162]
  PIN rw0_rd_out[163]
    DIRECTION OUTPUT ;
    USE SIGNAL ;
    SHAPE ABUTMENT ;
    PORT
      LAYER met2 ;
      RECT 377.590 290.620 377.730 291.040 ;
    END
  END rw0_rd_out[163]
  PIN rw0_rd_out[164]
    DIRECTION OUTPUT ;
    USE SIGNAL ;
    SHAPE ABUTMENT ;
    PORT
      LAYER met2 ;
      RECT 379.890 290.620 380.030 291.040 ;
    END
  END rw0_rd_out[164]
  PIN rw0_rd_out[165]
    DIRECTION OUTPUT ;
    USE SIGNAL ;
    SHAPE ABUTMENT ;
    PORT
      LAYER met2 ;
      RECT 382.190 290.620 382.330 291.040 ;
    END
  END rw0_rd_out[165]
  PIN rw0_rd_out[166]
    DIRECTION OUTPUT ;
    USE SIGNAL ;
    SHAPE ABUTMENT ;
    PORT
      LAYER met2 ;
      RECT 384.490 290.620 384.630 291.040 ;
    END
  END rw0_rd_out[166]
  PIN rw0_rd_out[167]
    DIRECTION OUTPUT ;
    USE SIGNAL ;
    SHAPE ABUTMENT ;
    PORT
      LAYER met2 ;
      RECT 386.790 290.620 386.930 291.040 ;
    END
  END rw0_rd_out[167]
  PIN rw0_rd_out[168]
    DIRECTION OUTPUT ;
    USE SIGNAL ;
    SHAPE ABUTMENT ;
    PORT
      LAYER met2 ;
      RECT 389.090 290.620 389.230 291.040 ;
    END
  END rw0_rd_out[168]
  PIN rw0_rd_out[169]
    DIRECTION OUTPUT ;
    USE SIGNAL ;
    SHAPE ABUTMENT ;
    PORT
      LAYER met2 ;
      RECT 391.390 290.620 391.530 291.040 ;
    END
  END rw0_rd_out[169]
  PIN rw0_rd_out[170]
    DIRECTION OUTPUT ;
    USE SIGNAL ;
    SHAPE ABUTMENT ;
    PORT
      LAYER met2 ;
      RECT 393.690 290.620 393.830 291.040 ;
    END
  END rw0_rd_out[170]
  PIN rw0_rd_out[171]
    DIRECTION OUTPUT ;
    USE SIGNAL ;
    SHAPE ABUTMENT ;
    PORT
      LAYER met2 ;
      RECT 395.990 290.620 396.130 291.040 ;
    END
  END rw0_rd_out[171]
  PIN rw0_rd_out[172]
    DIRECTION OUTPUT ;
    USE SIGNAL ;
    SHAPE ABUTMENT ;
    PORT
      LAYER met2 ;
      RECT 398.290 290.620 398.430 291.040 ;
    END
  END rw0_rd_out[172]
  PIN rw0_rd_out[173]
    DIRECTION OUTPUT ;
    USE SIGNAL ;
    SHAPE ABUTMENT ;
    PORT
      LAYER met2 ;
      RECT 400.590 290.620 400.730 291.040 ;
    END
  END rw0_rd_out[173]
  PIN rw0_rd_out[174]
    DIRECTION OUTPUT ;
    USE SIGNAL ;
    SHAPE ABUTMENT ;
    PORT
      LAYER met2 ;
      RECT 402.890 290.620 403.030 291.040 ;
    END
  END rw0_rd_out[174]
  PIN rw0_rd_out[175]
    DIRECTION OUTPUT ;
    USE SIGNAL ;
    SHAPE ABUTMENT ;
    PORT
      LAYER met2 ;
      RECT 405.190 290.620 405.330 291.040 ;
    END
  END rw0_rd_out[175]
  PIN rw0_rd_out[176]
    DIRECTION OUTPUT ;
    USE SIGNAL ;
    SHAPE ABUTMENT ;
    PORT
      LAYER met2 ;
      RECT 407.490 290.620 407.630 291.040 ;
    END
  END rw0_rd_out[176]
  PIN rw0_rd_out[177]
    DIRECTION OUTPUT ;
    USE SIGNAL ;
    SHAPE ABUTMENT ;
    PORT
      LAYER met2 ;
      RECT 409.790 290.620 409.930 291.040 ;
    END
  END rw0_rd_out[177]
  PIN rw0_rd_out[178]
    DIRECTION OUTPUT ;
    USE SIGNAL ;
    SHAPE ABUTMENT ;
    PORT
      LAYER met2 ;
      RECT 412.090 290.620 412.230 291.040 ;
    END
  END rw0_rd_out[178]
  PIN rw0_rd_out[179]
    DIRECTION OUTPUT ;
    USE SIGNAL ;
    SHAPE ABUTMENT ;
    PORT
      LAYER met2 ;
      RECT 414.390 290.620 414.530 291.040 ;
    END
  END rw0_rd_out[179]
  PIN rw0_rd_out[180]
    DIRECTION OUTPUT ;
    USE SIGNAL ;
    SHAPE ABUTMENT ;
    PORT
      LAYER met2 ;
      RECT 416.690 290.620 416.830 291.040 ;
    END
  END rw0_rd_out[180]
  PIN rw0_rd_out[181]
    DIRECTION OUTPUT ;
    USE SIGNAL ;
    SHAPE ABUTMENT ;
    PORT
      LAYER met2 ;
      RECT 418.990 290.620 419.130 291.040 ;
    END
  END rw0_rd_out[181]
  PIN rw0_rd_out[182]
    DIRECTION OUTPUT ;
    USE SIGNAL ;
    SHAPE ABUTMENT ;
    PORT
      LAYER met2 ;
      RECT 421.290 290.620 421.430 291.040 ;
    END
  END rw0_rd_out[182]
  PIN rw0_rd_out[183]
    DIRECTION OUTPUT ;
    USE SIGNAL ;
    SHAPE ABUTMENT ;
    PORT
      LAYER met2 ;
      RECT 423.590 290.620 423.730 291.040 ;
    END
  END rw0_rd_out[183]
  PIN rw0_addr_in[0]
    DIRECTION INPUT ;
    USE SIGNAL ;
    SHAPE ABUTMENT ;
    PORT
      LAYER met3 ;
      RECT 0.000 254.170 0.900 254.470 ;
    END
  END rw0_addr_in[0]
  PIN rw0_addr_in[1]
    DIRECTION INPUT ;
    USE SIGNAL ;
    SHAPE ABUTMENT ;
    PORT
      LAYER met3 ;
      RECT 0.000 256.890 0.900 257.190 ;
    END
  END rw0_addr_in[1]
  PIN rw0_addr_in[2]
    DIRECTION INPUT ;
    USE SIGNAL ;
    SHAPE ABUTMENT ;
    PORT
      LAYER met3 ;
      RECT 0.000 259.610 0.900 259.910 ;
    END
  END rw0_addr_in[2]
  PIN rw0_addr_in[3]
    DIRECTION INPUT ;
    USE SIGNAL ;
    SHAPE ABUTMENT ;
    PORT
      LAYER met3 ;
      RECT 513.840 254.170 514.740 254.470 ;
    END
  END rw0_addr_in[3]
  PIN rw0_addr_in[4]
    DIRECTION INPUT ;
    USE SIGNAL ;
    SHAPE ABUTMENT ;
    PORT
      LAYER met3 ;
      RECT 513.840 256.890 514.740 257.190 ;
    END
  END rw0_addr_in[4]
  PIN rw0_addr_in[5]
    DIRECTION INPUT ;
    USE SIGNAL ;
    SHAPE ABUTMENT ;
    PORT
      LAYER met3 ;
      RECT 513.840 259.610 514.740 259.910 ;
    END
  END rw0_addr_in[5]
  PIN rw0_we_in
    DIRECTION INPUT ;
    USE SIGNAL ;
    SHAPE ABUTMENT ;
    PORT
      LAYER met2 ;
      RECT 425.890 290.620 426.030 291.040 ;
    END
  END rw0_we_in
  PIN rw0_ce_in
    DIRECTION INPUT ;
    USE SIGNAL ;
    SHAPE ABUTMENT ;
    PORT
      LAYER met2 ;
      RECT 428.190 290.620 428.330 291.040 ;
    END
  END rw0_ce_in
  PIN rw0_clk
    DIRECTION INPUT ;
    USE SIGNAL ;
    SHAPE ABUTMENT ;
    PORT
      LAYER met2 ;
      RECT 430.490 290.620 430.630 291.040 ;
    END
  END rw0_clk
  PIN VSS
    DIRECTION INOUT ;
    USE GROUND ;
    PORT
      LAYER met4 ;
      RECT 2.160 4.080 3.360 286.960 ;
      RECT 13.040 4.080 14.240 286.960 ;
      RECT 23.920 4.080 25.120 286.960 ;
      RECT 34.800 4.080 36.000 286.960 ;
      RECT 45.680 4.080 46.880 286.960 ;
      RECT 56.560 4.080 57.760 286.960 ;
      RECT 67.440 4.080 68.640 286.960 ;
      RECT 78.320 4.080 79.520 286.960 ;
      RECT 89.200 4.080 90.400 286.960 ;
      RECT 100.080 4.080 101.280 286.960 ;
      RECT 110.960 4.080 112.160 286.960 ;
      RECT 121.840 4.080 123.040 286.960 ;
      RECT 132.720 4.080 133.920 286.960 ;
      RECT 143.600 4.080 144.800 286.960 ;
      RECT 154.480 4.080 155.680 286.960 ;
      RECT 165.360 4.080 166.560 286.960 ;
      RECT 176.240 4.080 177.440 286.960 ;
      RECT 187.120 4.080 188.320 286.960 ;
      RECT 198.000 4.080 199.200 286.960 ;
      RECT 208.880 4.080 210.080 286.960 ;
      RECT 219.760 4.080 220.960 286.960 ;
      RECT 230.640 4.080 231.840 286.960 ;
      RECT 241.520 4.080 242.720 286.960 ;
      RECT 252.400 4.080 253.600 286.960 ;
      RECT 263.280 4.080 264.480 286.960 ;
      RECT 274.160 4.080 275.360 286.960 ;
      RECT 285.040 4.080 286.240 286.960 ;
      RECT 295.920 4.080 297.120 286.960 ;
      RECT 306.800 4.080 308.000 286.960 ;
      RECT 317.680 4.080 318.880 286.960 ;
      RECT 328.560 4.080 329.760 286.960 ;
      RECT 339.440 4.080 340.640 286.960 ;
      RECT 350.320 4.080 351.520 286.960 ;
      RECT 361.200 4.080 362.400 286.960 ;
      RECT 372.080 4.080 373.280 286.960 ;
      RECT 382.960 4.080 384.160 286.960 ;
      RECT 393.840 4.080 395.040 286.960 ;
      RECT 404.720 4.080 405.920 286.960 ;
      RECT 415.600 4.080 416.800 286.960 ;
      RECT 426.480 4.080 427.680 286.960 ;
      RECT 437.360 4.080 438.560 286.960 ;
      RECT 448.240 4.080 449.440 286.960 ;
      RECT 459.120 4.080 460.320 286.960 ;
      RECT 470.000 4.080 471.200 286.960 ;
      RECT 480.880 4.080 482.080 286.960 ;
      RECT 491.760 4.080 492.960 286.960 ;
      RECT 502.640 4.080 503.840 286.960 ;
      RECT 513.520 4.080 514.720 286.960 ;
    END
  END VSS
  PIN VDD
    DIRECTION INOUT ;
    USE POWER ;
    PORT
      LAYER met4 ;
      RECT 7.600 4.080 8.800 286.960 ;
      RECT 18.480 4.080 19.680 286.960 ;
      RECT 29.360 4.080 30.560 286.960 ;
      RECT 40.240 4.080 41.440 286.960 ;
      RECT 51.120 4.080 52.320 286.960 ;
      RECT 62.000 4.080 63.200 286.960 ;
      RECT 72.880 4.080 74.080 286.960 ;
      RECT 83.760 4.080 84.960 286.960 ;
      RECT 94.640 4.080 95.840 286.960 ;
      RECT 105.520 4.080 106.720 286.960 ;
      RECT 116.400 4.080 117.600 286.960 ;
      RECT 127.280 4.080 128.480 286.960 ;
      RECT 138.160 4.080 139.360 286.960 ;
      RECT 149.040 4.080 150.240 286.960 ;
      RECT 159.920 4.080 161.120 286.960 ;
      RECT 170.800 4.080 172.000 286.960 ;
      RECT 181.680 4.080 182.880 286.960 ;
      RECT 192.560 4.080 193.760 286.960 ;
      RECT 203.440 4.080 204.640 286.960 ;
      RECT 214.320 4.080 215.520 286.960 ;
      RECT 225.200 4.080 226.400 286.960 ;
      RECT 236.080 4.080 237.280 286.960 ;
      RECT 246.960 4.080 248.160 286.960 ;
      RECT 257.840 4.080 259.040 286.960 ;
      RECT 268.720 4.080 269.920 286.960 ;
      RECT 279.600 4.080 280.800 286.960 ;
      RECT 290.480 4.080 291.680 286.960 ;
      RECT 301.360 4.080 302.560 286.960 ;
      RECT 312.240 4.080 313.440 286.960 ;
      RECT 323.120 4.080 324.320 286.960 ;
      RECT 334.000 4.080 335.200 286.960 ;
      RECT 344.880 4.080 346.080 286.960 ;
      RECT 355.760 4.080 356.960 286.960 ;
      RECT 366.640 4.080 367.840 286.960 ;
      RECT 377.520 4.080 378.720 286.960 ;
      RECT 388.400 4.080 389.600 286.960 ;
      RECT 399.280 4.080 400.480 286.960 ;
      RECT 410.160 4.080 411.360 286.960 ;
      RECT 421.040 4.080 422.240 286.960 ;
      RECT 431.920 4.080 433.120 286.960 ;
      RECT 442.800 4.080 444.000 286.960 ;
      RECT 453.680 4.080 454.880 286.960 ;
      RECT 464.560 4.080 465.760 286.960 ;
      RECT 475.440 4.080 476.640 286.960 ;
      RECT 486.320 4.080 487.520 286.960 ;
      RECT 497.200 4.080 498.400 286.960 ;
      RECT 508.080 4.080 509.280 286.960 ;
    END
  END VDD
  OBS
    LAYER met1 ;
    RECT 0 0 514.740 291.040 ;
    LAYER met2 ;
    RECT 0 0 514.740 291.040 ;
    LAYER met3 ;
    RECT 0 0 514.740 291.040 ;
    LAYER met4 ;
    RECT 0 0 514.740 291.040 ;
  END
END fakeram_64x184_1rw

END LIBRARY
